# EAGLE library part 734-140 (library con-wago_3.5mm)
Serie 734, Stiftleiste (für Leiterplatten) Einlötstift gerade 1 x 1 mm / Series 734, Male header (for PCBs) Straight solder pin 1 x 1 mm Polzahl / Pole No.: 10 Rastermaß / Pitch: 3.5 mm Bemessungsspannung / Rated Voltage: 160 V Nennstrom / Nominal Current: 10 A Lötstiftlänge: / Solder Pin Length: 4.5 mm Farbe / Color: lichtgrau / light gray Stand: 01.01.2012. Die jeweils aktuellen Daten zu diesem Artikel finden Sie in unserem Produktkatalog, den Sie unter www.wago.com einsehen können. As of: 01/01/2012. Please find the newest data for this article in our product catalogue, which can be viewed under www.wago.com.

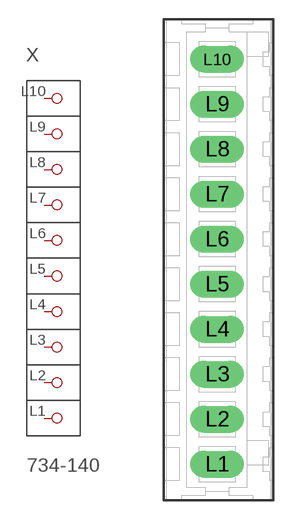
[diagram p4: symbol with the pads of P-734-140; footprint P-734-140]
Designator prefix X

## 734-140  [P-734-140]
L1  P1.1
L2  P2
L3  P3
L4  P4
L5  P5
L6  P6
L7  P7
L8  P8
L9  P9
L10  P10

## Footprint P-734-140 (pad centres in mm)
drill 1.4 long: L1 -0.1,-15.9; L2 -0.1,-12.4; L3 -0.1,-8.9; L4 -0.1,-5.4; L5 -0.1,-1.9; L6 -0.1,1.6; L7 -0.1,5.1; L8 -0.1,8.6; L9 -0.1,12.1; L10 -0.1,15.6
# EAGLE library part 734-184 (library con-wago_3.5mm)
Serie 734, Stiftleiste (für Leiterplatten) Einlötstift abgewinkelt 1 x 1 mm / Series 734, Male header (for PCBs) Angled solder pin 1 x 1 mm Polzahl / Pole No.: 24 Rastermaß / Pitch: 3.5 mm Bemessungsspannung / Rated Voltage: 160 V Nennstrom / Nominal Current: 10 A Lötstiftlänge: / Solder Pin Length: 3.8 mm Farbe / Color: lichtgrau / light gray Stand: 01.01.2012. Die jeweils aktuellen Daten zu diesem Artikel finden Sie in unserem Produktkatalog, den Sie unter www.wago.com einsehen können. As of: 01/01/2012. Please find the newest data for this article in our product catalogue, which can be viewed under www.wago.com.

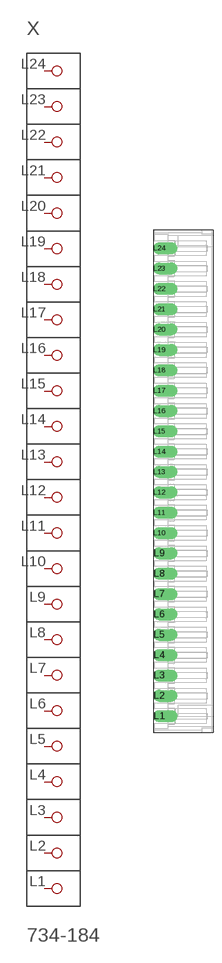
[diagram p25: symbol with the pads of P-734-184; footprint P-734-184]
Designator prefix X

## 734-184  [P-734-184]
L1  P1
L2  P2
L3  P3
L4  P4
L5  P5
L6  P6
L7  P7
L8  P8
L9  P9
L10  P10
L11  P11
L12  P12
L13  P13
L14  P14
L15  P15
L16  P16
L17  P17
L18  P18
L19  P19
L20  P20
L21  P21
L22  P22
L23  P23
L24  P24

## Footprint P-734-184 (pad centres in mm)
drill 1.4 pad 2 offset: L1 -4.15,-40.4; L2 -4.15,-36.9; L3 -4.15,-33.4; L4 -4.15,-29.9; L5 -4.15,-26.4; L6 -4.15,-22.9; L7 -4.15,-19.4; L8 -4.15,-15.9; L9 -4.15,-12.4; L10 -4.15,-8.9; L11 -4.15,-5.4; L12 -4.15,-1.9; L13 -4.15,1.6; L14 -4.15,5.1; L15 -4.15,8.6; L16 -4.15,12.1; L17 -4.15,15.6; L18 -4.15,19.1; L19 -4.15,22.6; L20 -4.15,26.1; L21 -4.15,29.6; L22 -4.15,33.1; L23 -4.15,36.6; L24 -4.15,40.1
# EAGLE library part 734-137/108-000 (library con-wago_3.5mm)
Serie 734, Stiftleiste (für Leiterplatten) Einlötstift gerade 1 x 1 mm / Series 734, Male header (for PCBs) Straight solder pin 1 x 1 mm Polzahl / Pole No.: 7 Bemessungsspannung / Rated Voltage: 160 V Nennstrom / Nominal Current: 10 A Lötstiftlänge: / Solder Pin Length: 4.5 mm Farbe / Color: lichtgrau / light gray Stand: 01.01.2012. Die jeweils aktuellen Daten zu diesem Artikel finden Sie in unserem Produktkatalog, den Sie unter www.wago.com einsehen können. As of: 01/01/2012. Please find the newest data for this article in our product catalogue, which can be viewed under www.wago.com.

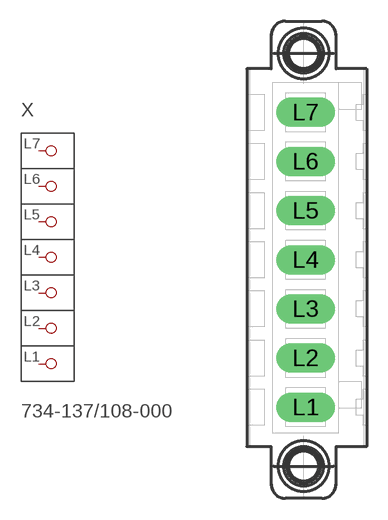
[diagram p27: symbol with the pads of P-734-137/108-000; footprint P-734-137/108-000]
Designator prefix X

## 734-137/108-000  [P-734-137/108-000]
L1  P1
L2  P2
L3  P3
L4  P4
L5  P5
L6  P6
L7  P7

## Footprint P-734-137/108-000 (pad centres in mm)
drill 1.4 long: L1 -0.075,-10.5; L2 -0.075,-7; L3 -0.075,-3.5; L4 -0.075,0; L5 -0.075,3.5; L6 -0.075,7; L7 -0.075,10.5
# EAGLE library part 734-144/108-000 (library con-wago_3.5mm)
Serie 734, Stiftleiste mit geraden Einlötstiften / Series 734, Male connector with straight solder pins Polzahl / Pole No.: 14 Lötstiftlänge: / Solder Pin Length: 4.5 mm Farbe / Color: lichtgrau / light gray Stand: 01.01.2012. Die jeweils aktuellen Daten zu diesem Artikel finden Sie in unserem Produktkatalog, den Sie unter www.wago.com einsehen können. As of: 01/01/2012. Please find the newest data for this article in our product catalogue, which can be viewed under www.wago.com.

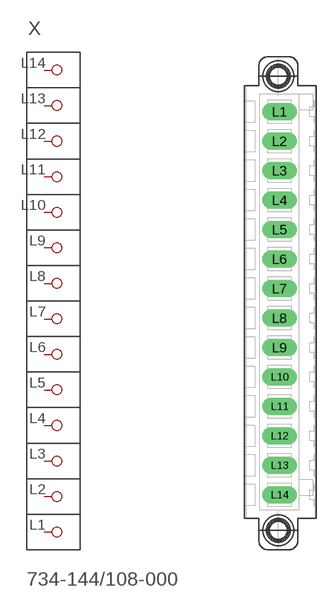
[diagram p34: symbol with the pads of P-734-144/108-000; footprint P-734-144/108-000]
Designator prefix X

## 734-144/108-000  [P-734-144/108-000]
L1  P1
L2  P2
L3  P3
L4  P4
L5  P5
L6  P6
L7  P7
L8  P8
L9  P9
L10  P10
L11  P11
L12  P12
L13  P13
L14  P14

## Footprint P-734-144/108-000 (pad centres in mm)
drill 1.4 long: L1 -0.075,22.75; L2 -0.075,19.25; L3 -0.075,15.75; L4 -0.075,12.25; L5 -0.075,8.75; L6 -0.075,5.25; L7 -0.075,1.75; L8 -0.075,-1.75; L9 -0.075,-5.25; L10 -0.075,-8.75; L11 -0.075,-12.25; L12 -0.075,-15.75; L13 -0.075,-19.25; L14 -0.075,-22.75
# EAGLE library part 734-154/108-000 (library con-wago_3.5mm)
Serie 734, Stiftleiste (für Leiterplatten) Einlötstift gerade 1 x 1 mm / Series 734, Male header (for PCBs) Straight solder pin 1 x 1 mm Polzahl / Pole No.: 24 Bemessungsspannung / Rated Voltage: 160 V Nennstrom / Nominal Current: 10 A Lötstiftlänge: / Solder Pin Length: 4.5 mm Farbe / Color: lichtgrau / light gray Stand: 01.01.2012. Die jeweils aktuellen Daten zu diesem Artikel finden Sie in unserem Produktkatalog, den Sie unter www.wago.com einsehen können. As of: 01/01/2012. Please find the newest data for this article in our product catalogue, which can be viewed under www.wago.com.

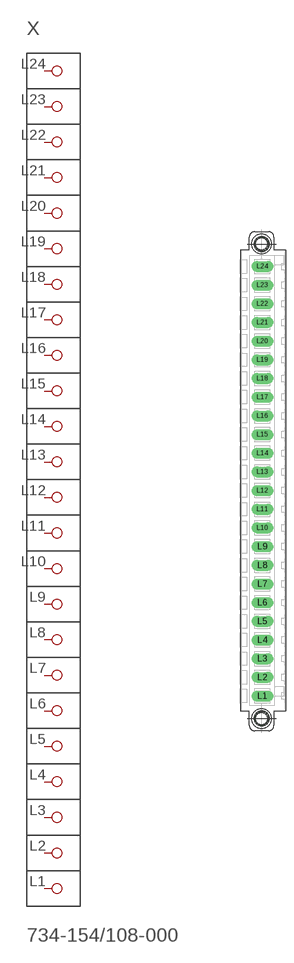
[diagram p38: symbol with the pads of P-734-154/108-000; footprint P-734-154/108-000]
Designator prefix X

## 734-154/108-000  [P-734-154/108-000]
L1  P1
L2  P2
L3  P3
L4  P4
L5  P5
L6  P6
L7  P7
L8  P8
L9  P9
L10  P10
L11  P11
L12  P12
L13  P13
L14  P14
L15  P15
L16  P16
L17  P17
L18  P18
L19  P19
L20  P20
L21  P21
L22  P22
L23  P23
L24  P24

## Footprint P-734-154/108-000 (pad centres in mm)
drill 1.4 long: L1 -0.075,-40.25; L2 -0.075,-36.75; L3 -0.075,-33.25; L4 -0.075,-29.75; L5 -0.075,-26.25; L6 -0.075,-22.75; L7 -0.075,-19.25; L8 -0.075,-15.75; L9 -0.075,-12.25; L10 -0.075,-8.75; L11 -0.075,-5.25; L12 -0.075,-1.75; L13 -0.075,1.75; L14 -0.075,5.25; L15 -0.075,8.75; L16 -0.075,12.25; L17 -0.075,15.75; L18 -0.075,19.25; L19 -0.075,22.75; L20 -0.075,26.25; L21 -0.075,29.75; L22 -0.075,33.25; L23 -0.075,36.75; L24 -0.075,40.25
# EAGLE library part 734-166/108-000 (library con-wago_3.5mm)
Serie 734, Stiftleiste (für Leiterplatten) Einlötstift abgewinkelt 1 x 1 mm / Series 734, Male header (for PCBs) Angled solder pin 1 x 1 mm Polzahl / Pole No.: 6 Bemessungsspannung / Rated Voltage: 160 V Nennstrom / Nominal Current: 10 A Lötstiftlänge: / Solder Pin Length: 3.8 mm Farbe / Color: lichtgrau / light gray Stand: 01.01.2012. Die jeweils aktuellen Daten zu diesem Artikel finden Sie in unserem Produktkatalog, den Sie unter www.wago.com einsehen können. As of: 01/01/2012. Please find the newest data for this article in our product catalogue, which can be viewed under www.wago.com.

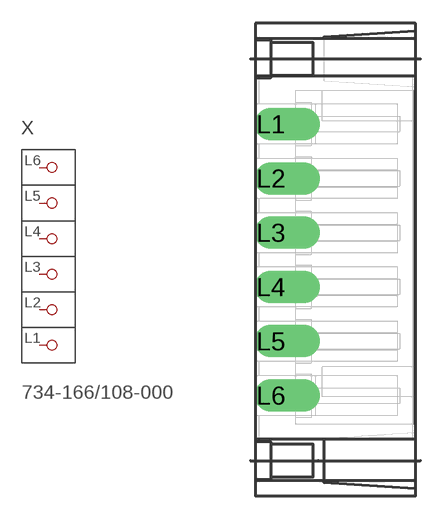
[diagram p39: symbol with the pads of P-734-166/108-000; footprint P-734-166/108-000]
Designator prefix X

## 734-166/108-000  [P-734-166/108-000]
L1  P1
L2  P2
L3  P3
L4  P4
L5  P5
L6  P6

## Footprint P-734-166/108-000 (pad centres in mm)
drill 1.4 pad 2 offset: L1 -4.15,8.75; L2 -4.15,5.25; L3 -4.15,1.75; L4 -4.15,-1.75; L5 -4.15,-5.25; L6 -4.15,-8.75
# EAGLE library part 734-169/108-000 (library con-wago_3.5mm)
Serie 734, Stiftleiste (für Leiterplatten) Einlötstift abgewinkelt 1 x 1 mm / Series 734, Male header (for PCBs) Angled solder pin 1 x 1 mm Polzahl / Pole No.: 9 Bemessungsspannung / Rated Voltage: 160 V Nennstrom / Nominal Current: 10 A Lötstiftlänge: / Solder Pin Length: 3.8 mm Farbe / Color: lichtgrau / light gray Stand: 01.01.2012. Die jeweils aktuellen Daten zu diesem Artikel finden Sie in unserem Produktkatalog, den Sie unter www.wago.com einsehen können. As of: 01/01/2012. Please find the newest data for this article in our product catalogue, which can be viewed under www.wago.com.

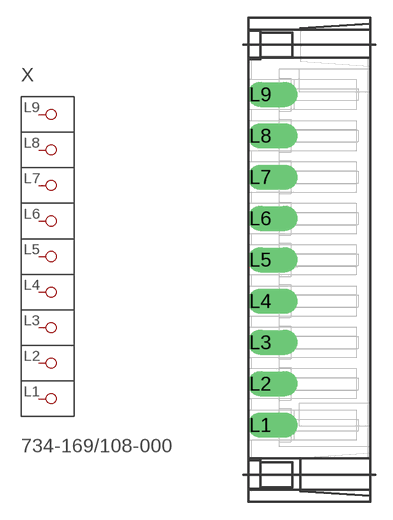
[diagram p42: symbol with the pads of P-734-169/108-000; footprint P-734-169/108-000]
Designator prefix X

## 734-169/108-000  [P-734-169/108-000]
L1  P1
L2  P2
L3  P3
L4  P4
L5  P5
L6  P6
L7  P7
L8  P8
L9  P9

## Footprint P-734-169/108-000 (pad centres in mm)
drill 1.4 pad 2 offset: L1 -4.15,-14; L2 -4.15,-10.5; L3 -4.15,-7; L4 -4.15,-3.5; L5 -4.15,0; L6 -4.15,3.5; L7 -4.15,7; L8 -4.15,10.5; L9 -4.15,14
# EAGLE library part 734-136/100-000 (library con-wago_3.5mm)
Serie 734, Stiftleiste (für Leiterplatten) Einpressstift 0,6 x 0,6 mm / Series 734, Male header (for PCBs) Press-in pin 0.6 x 0.6 mm Polzahl / Pole No.: 6 Rastermaß / Pitch: 3.5 mm Bemessungsspannung / Rated Voltage: 160 V Nennstrom / Nominal Current: 8 A Farbe / Color: lichtgrau / light gray Stand: 01.01.2012. Die jeweils aktuellen Daten zu diesem Artikel finden Sie in unserem Produktkatalog, den Sie unter www.wago.com einsehen können. As of: 01/01/2012. Please find the newest data for this article in our product catalogue, which can be viewed under www.wago.com.

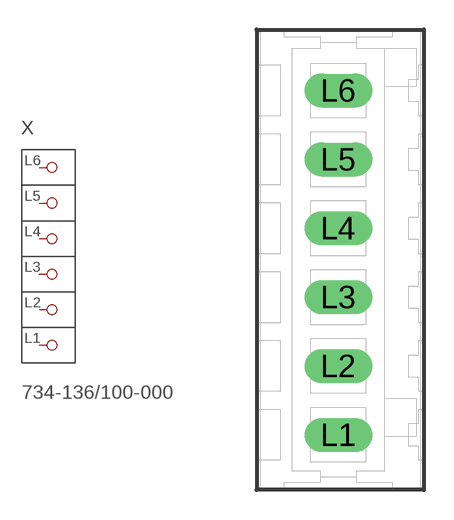
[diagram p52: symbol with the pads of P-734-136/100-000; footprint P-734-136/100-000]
Designator prefix X

## 734-136/100-000  [P-734-136/100-000]
L1  P1
L2  P2
L3  P3
L4  P4
L5  P5
L6  P6

## Footprint P-734-136/100-000 (pad centres in mm)
drill 1.15 long: L1 -0.1,-8.9; L2 -0.1,-5.4; L3 -0.1,-1.9; L4 -0.1,1.6; L5 -0.1,5.1; L6 -0.1,8.6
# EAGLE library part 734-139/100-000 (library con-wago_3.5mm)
Serie 734, Stiftleiste (für Leiterplatten) Einpressstift 0,6 x 0,6 mm / Series 734, Male header (for PCBs) Press-in pin 0.6 x 0.6 mm Polzahl / Pole No.: 9 Rastermaß / Pitch: 3.5 mm Bemessungsspannung / Rated Voltage: 160 V Nennstrom / Nominal Current: 8 A Farbe / Color: lichtgrau / light gray Stand: 01.01.2012. Die jeweils aktuellen Daten zu diesem Artikel finden Sie in unserem Produktkatalog, den Sie unter www.wago.com einsehen können. As of: 01/01/2012. Please find the newest data for this article in our product catalogue, which can be viewed under www.wago.com.

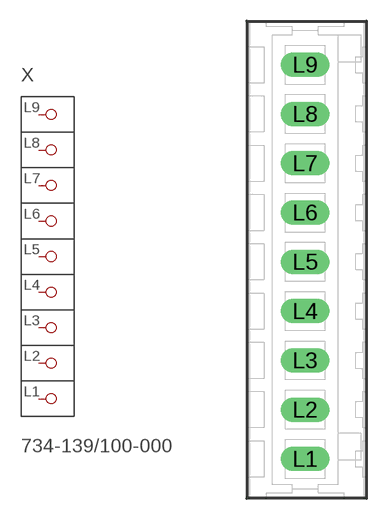
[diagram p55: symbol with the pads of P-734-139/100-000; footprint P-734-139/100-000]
Designator prefix X

## 734-139/100-000  [P-734-139/100-000]
L1  P1
L2  P2
L3  P3
L4  P4
L5  P5
L6  P6
L7  P7
L8  P8
L9  P9

## Footprint P-734-139/100-000 (pad centres in mm)
drill 1.15 long: L1 -0.1,-14.15; L2 -0.1,-10.65; L3 -0.1,-7.15; L4 -0.1,-3.65; L5 -0.1,-0.15; L6 -0.1,3.35; L7 -0.1,6.85; L8 -0.1,10.35; L9 -0.1,13.85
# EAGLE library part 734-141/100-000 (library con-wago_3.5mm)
Serie 734, Stiftleiste (für Leiterplatten) Einpressstift 0,6 x 0,6 mm / Series 734, Male header (for PCBs) Press-in pin 0.6 x 0.6 mm Polzahl / Pole No.: 11 Bemessungsspannung / Rated Voltage: 160 V Nennstrom / Nominal Current: 10 A Farbe / Color: lichtgrau / light gray Stand: 01.01.2012. Die jeweils aktuellen Daten zu diesem Artikel finden Sie in unserem Produktkatalog, den Sie unter www.wago.com einsehen können. As of: 01/01/2012. Please find the newest data for this article in our product catalogue, which can be viewed under www.wago.com.

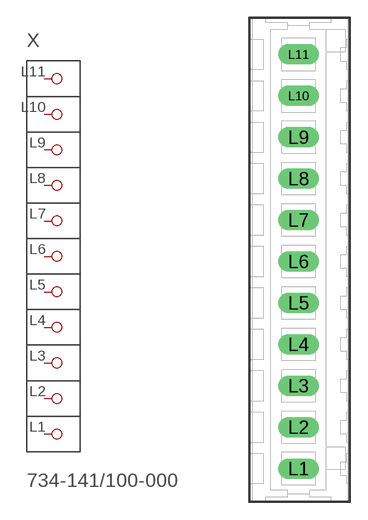
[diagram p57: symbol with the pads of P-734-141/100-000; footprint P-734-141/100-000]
Designator prefix X

## 734-141/100-000  [P-734-141/100-000]
L1  P1
L2  P2
L3  P3
L4  P4
L5  P5
L6  P6
L7  P7
L8  P8
L9  P9
L10  P10
L11  P11

## Footprint P-734-141/100-000 (pad centres in mm)
drill 1.15 long: L1 -0.1,-17.65; L2 -0.1,-14.15; L3 -0.1,-10.65; L4 -0.1,-7.15; L5 -0.1,-3.65; L6 -0.1,-0.15; L7 -0.1,3.35; L8 -0.1,6.85; L9 -0.1,10.35; L10 -0.1,13.85; L11 -0.1,17.35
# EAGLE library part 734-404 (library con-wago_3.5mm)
Serie 734, Doppelstock-Stiftleisten Einlötstift abgewinkelt 1 x 1 mm / Series 734, Double-deck male headers Angled solder pin 1 x 1 mm Polzahl / Pole No.: 4 Rastermaß / Pitch: 3.5 mm Bemessungsspannung / Rated Voltage: 160 V Nennstrom / Nominal Current: 10 A Lötstiftlänge: / Solder Pin Length: 3.6 mm Farbe / Color: lichtgrau / light gray Stand: 01.01.2012. Die jeweils aktuellen Daten zu diesem Artikel finden Sie in unserem Produktkatalog, den Sie unter www.wago.com einsehen können. As of: 01/01/2012. Please find the newest data for this article in our product catalogue, which can be viewed under www.wago.com.

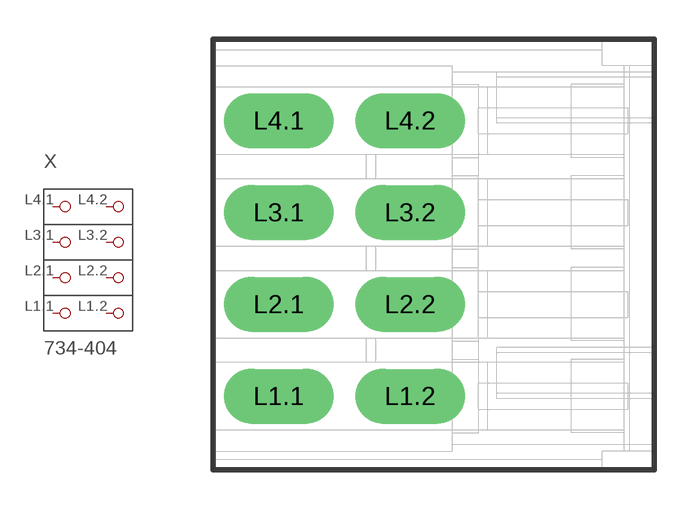
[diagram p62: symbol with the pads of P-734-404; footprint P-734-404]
Designator prefix X

## 734-404  [P-734-404]
L1.1  P1.1
L1.2  P1.2
L2.1  P2.1
L2.2  P2.2
L3.1  P3.1
L3.2  P3.2
L4.1  P4.1
L4.2  P4.2

## Footprint P-734-404 (pad centres in mm)
drill 1.4 long: L1.1 -5.9,-5.4; L1.2 -0.9,-5.4; L2.1 -5.9,-1.9; L2.2 -0.9,-1.9; L3.1 -5.9,1.6; L3.2 -0.9,1.6; L4.1 -5.9,5.1; L4.2 -0.9,5.1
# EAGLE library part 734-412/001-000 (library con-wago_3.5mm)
Serie 734, Doppelstock-Stiftleisten Einlötstift abgewinkelt 1 x 1 mm / Series 734, Double-deck male headers Angled solder pin 1 x 1 mm Polzahl / Pole No.: 12 Rastermaß / Pitch: 3.5 mm Bemessungsspannung / Rated Voltage: 160 V Nennstrom / Nominal Current: 10 A Lötstiftlänge: / Solder Pin Length: 3.6 mm Farbe / Color: lichtgrau / light gray Stand: 01.01.2012. Die jeweils aktuellen Daten zu diesem Artikel finden Sie in unserem Produktkatalog, den Sie unter www.wago.com einsehen können. As of: 01/01/2012. Please find the newest data for this article in our product catalogue, which can be viewed under www.wago.com.

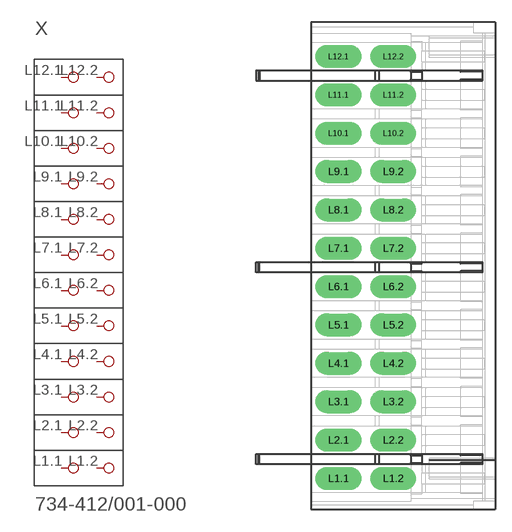
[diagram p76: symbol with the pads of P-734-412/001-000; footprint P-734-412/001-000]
Designator prefix X

## 734-412/001-000  [P-734-412/001-000]
L1.1  P1.1
L1.2  P1.2
L2.1  P2.1
L2.2  P2.2
L3.1  P3.1
L3.2  P3.2
L4.1  P4.1
L4.2  P4.2
L5.1  P5.1
L5.2  P5.2
L6.1  P6.1
L6.2  P6.2
L7.1  P7.1
L7.2  P7.2
L8.1  P8.1
L8.2  P8.2
L9.1  P9.1
L9.2  P9.2
L10.1  P10.1
L10.2  P10.2
L11.1  P11.1
L11.2  P11.2
L12.1  P12.1
L12.2  P12.2

## Footprint P-734-412/001-000 (pad centres in mm)
drill 1.4 long: L1.1 -3.4,-19.4; L1.2 1.6,-19.4; L2.1 -3.4,-15.9; L2.2 1.6,-15.9; L3.1 -3.4,-12.4; L3.2 1.6,-12.4; L4.1 -3.4,-8.9; L4.2 1.6,-8.9; L5.1 -3.4,-5.4; L5.2 1.6,-5.4; L6.1 -3.4,-1.9; L6.2 1.6,-1.9; L7.1 -3.4,1.6; L7.2 1.6,1.6; L8.1 -3.4,5.1; L8.2 1.6,5.1; L9.1 -3.4,8.6; L9.2 1.6,8.6; L10.1 -3.4,12.1; L10.2 1.6,12.1; L11.1 -3.4,15.6; L11.2 1.6,15.6; L12.1 -3.4,19.1; L12.2 1.6,19.1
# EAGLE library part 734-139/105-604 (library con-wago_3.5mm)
Serie 734, Stiftleiste (für Leiterplatten) Einlötstift gerade 1 x 1 mm / Series 734, Male header (for PCBs) Straight solder pin 1 x 1 mm Polzahl / Pole No.: 9 Bemessungsspannung / Rated Voltage: 160 V Nennstrom / Nominal Current: 10 A Lötstiftlänge: / Solder Pin Length: 2.4 mm Farbe / Color: schwarz / black Stand: 01.01.2012. Die jeweils aktuellen Daten zu diesem Artikel finden Sie in unserem Produktkatalog, den Sie unter www.wago.com einsehen können. As of: 01/01/2012. Please find the newest data for this article in our product catalogue, which can be viewed under www.wago.com.

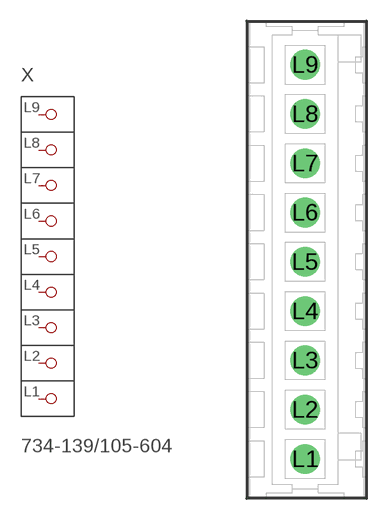
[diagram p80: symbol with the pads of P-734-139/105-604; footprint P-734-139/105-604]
Designator prefix X

## 734-139/105-604  [P-734-139/105-604]
L1  P1
L2  P2
L3  P3
L4  P4
L5  P5
L6  P6
L7  P7
L8  P8
L9  P9

## Footprint P-734-139/105-604 (pad centres in mm)
drill 1.4 round: L1 -0.1,-14.15; L2 -0.102,-10.645; L3 -0.1,-7.147; L4 -0.101,-3.646; L5 -0.111,-0.146; L6 -0.101,3.354; L7 -0.101,6.854; L8 -0.101,10.354; L9 -0.101,13.854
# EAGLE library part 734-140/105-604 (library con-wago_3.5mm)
Serie 734, Stiftleiste (für Leiterplatten) Einlötstift gerade 1 x 1 mm / Series 734, Male header (for PCBs) Straight solder pin 1 x 1 mm Polzahl / Pole No.: 10 Rastermaß / Pitch: 3.5 mm Bemessungsspannung / Rated Voltage: 160 V Nennstrom / Nominal Current: 10 A Lötstiftlänge: / Solder Pin Length: 2.4 mm Farbe / Color: schwarz / black Stand: 01.01.2012. Die jeweils aktuellen Daten zu diesem Artikel finden Sie in unserem Produktkatalog, den Sie unter www.wago.com einsehen können. As of: 01/01/2012. Please find the newest data for this article in our product catalogue, which can be viewed under www.wago.com.

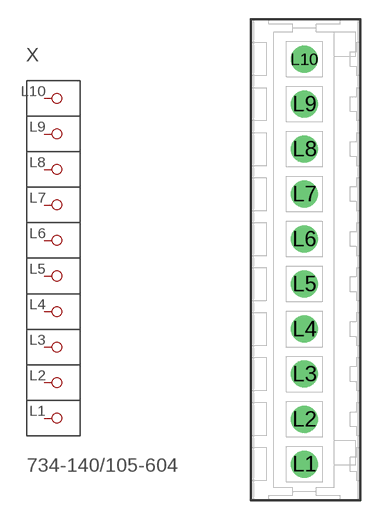
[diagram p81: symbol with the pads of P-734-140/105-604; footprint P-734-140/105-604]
Designator prefix X

## 734-140/105-604  [P-734-140/105-604]
L1  P1.1
L2  P2
L3  P3
L4  P4
L5  P5
L6  P6
L7  P7
L8  P8
L9  P9
L10  P10

## Footprint P-734-140/105-604 (pad centres in mm)
drill 1.4 round: L1 -0.1,-15.896; L2 -0.1,-12.404; L3 -0.093,-8.89; L4 -0.091,-5.392; L5 -0.092,-1.891; L6 -0.102,1.609; L7 -0.092,5.109; L8 -0.092,8.609; L9 -0.092,12.109; L10 -0.092,15.609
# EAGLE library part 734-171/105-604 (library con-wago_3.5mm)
Serie 734, Stiftleiste (für Leiterplatten) Einlötstift abgewinkelt 1 x 1 mm / Series 734, Male header (for PCBs) Angled solder pin 1 x 1 mm Polzahl / Pole No.: 11 Bemessungsspannung / Rated Voltage: 160 V Nennstrom / Nominal Current: 10 A Lötstiftlänge: / Solder Pin Length: 2.4 mm Farbe / Color: schwarz / black Stand: 01.01.2012. Die jeweils aktuellen Daten zu diesem Artikel finden Sie in unserem Produktkatalog, den Sie unter www.wago.com einsehen können. As of: 01/01/2012. Please find the newest data for this article in our product catalogue, which can be viewed under www.wago.com.

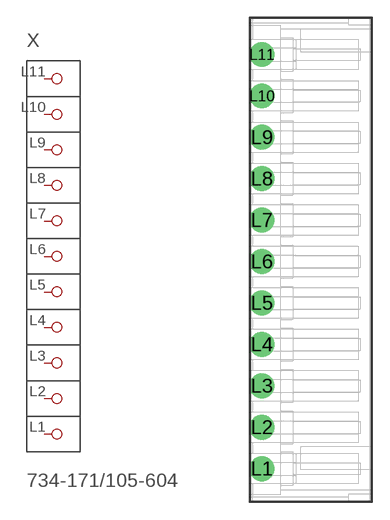
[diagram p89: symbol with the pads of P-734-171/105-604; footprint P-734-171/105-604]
Designator prefix X

## 734-171/105-604  [P-734-171/105-604]
L1  P1
L2  P2
L3  P3
L4  P4
L5  P5
L6  P6
L7  P7
L8  P8
L9  P9
L10  P10
L11  P11

## Footprint P-734-171/105-604 (pad centres in mm)
drill 1.4 round: L1 -4.15,-17.65; L2 -4.15,-14.15; L3 -4.15,-10.65; L4 -4.15,-7.15; L5 -4.15,-3.65; L6 -4.15,-0.15; L7 -4.15,3.35; L8 -4.15,6.85; L9 -4.15,10.35; L10 -4.15,13.85; L11 -4.15,17.35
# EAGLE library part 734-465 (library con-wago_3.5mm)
Serie 734, Federleiste mit geraden Einlötstiften / Series 734, Female connector with straight solder pins Polzahl / Pole No.: 5 Bemessungsspannung / Rated Voltage: 160 V Nennstrom / Nominal Current: 10 A Lötstiftlänge: / Solder Pin Length: 3.8 mm Farbe / Color: lichtgrau / light gray Stand: 01.01.2012. Die jeweils aktuellen Daten zu diesem Artikel finden Sie in unserem Produktkatalog, den Sie unter www.wago.com einsehen können. As of: 01/01/2012. Please find the newest data for this article in our product catalogue, which can be viewed under www.wago.com.

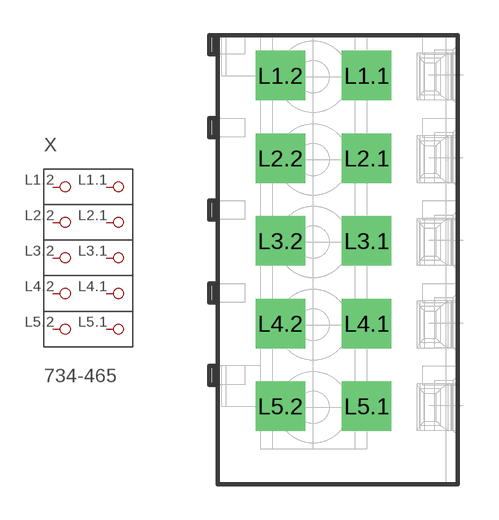
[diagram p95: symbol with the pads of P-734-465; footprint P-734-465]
Designator prefix X

## 734-465  [P-734-465]
L1.1  P1.1
L1.2  P1.2
L2.1  P2.1
L2.2  P2.2
L3.1  P3.1
L3.2  P3.2
L4.1  P4.1
L4.2  P4.2
L5.1  P5.1
L5.2  P5.2

## Footprint P-734-465 (pad centres in mm)
drill 1.4 square: L1.1 1.284,7.8; L1.2 -2.366,7.8; L2.1 1.284,4.3; L2.2 -2.366,4.3; L3.1 1.284,0.8; L3.2 -2.366,0.8; L4.1 1.284,-2.7; L4.2 -2.366,-2.7; L5.1 1.284,-6.2; L5.2 -2.366,-6.2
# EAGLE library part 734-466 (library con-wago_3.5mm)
Serie 734, Federleiste mit geraden Einlötstiften / Series 734, Female connector with straight solder pins Polzahl / Pole No.: 6 Bemessungsspannung / Rated Voltage: 160 V Nennstrom / Nominal Current: 10 A Lötstiftlänge: / Solder Pin Length: 3.8 mm Farbe / Color: lichtgrau / light gray Stand: 01.01.2012. Die jeweils aktuellen Daten zu diesem Artikel finden Sie in unserem Produktkatalog, den Sie unter www.wago.com einsehen können. As of: 01/01/2012. Please find the newest data for this article in our product catalogue, which can be viewed under www.wago.com.

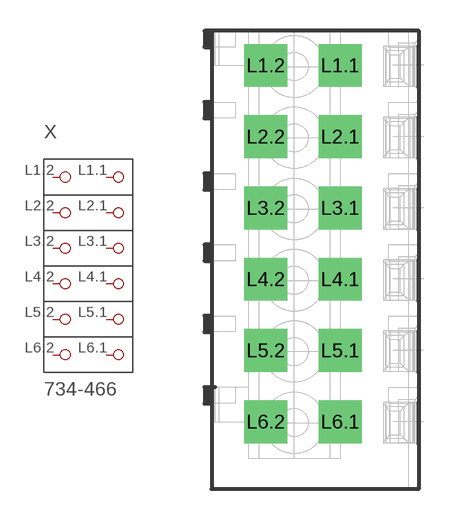
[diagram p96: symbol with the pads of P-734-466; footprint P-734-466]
Designator prefix X

## 734-466  [P-734-466]
L1.1  P1.1
L1.2  P1.2
L2.1  P2.1
L2.2  P2.2
L3.1  P3.1
L3.2  P3.2
L4.1  P4.1
L4.2  P4.2
L5.1  P5.1
L5.2  P5.2
L6.1  P6.1
L6.2  P6.2

## Footprint P-734-466 (pad centres in mm)
drill 1.4 square: L1.1 1.269,9.544; L1.2 -2.381,9.544; L2.1 1.269,6.044; L2.2 -2.381,6.044; L3.1 1.269,2.544; L3.2 -2.381,2.544; L4.1 1.269,-0.956; L4.2 -2.381,-0.956; L5.1 1.269,-4.456; L5.2 -2.381,-4.456; L6.1 1.269,-7.956; L6.2 -2.381,-7.956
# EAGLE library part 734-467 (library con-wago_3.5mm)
Serie 734, Federleiste mit geraden Einlötstiften / Series 734, Female connector with straight solder pins Polzahl / Pole No.: 7 Bemessungsspannung / Rated Voltage: 160 V Nennstrom / Nominal Current: 10 A Lötstiftlänge: / Solder Pin Length: 3.8 mm Farbe / Color: lichtgrau / light gray Stand: 01.01.2012. Die jeweils aktuellen Daten zu diesem Artikel finden Sie in unserem Produktkatalog, den Sie unter www.wago.com einsehen können. As of: 01/01/2012. Please find the newest data for this article in our product catalogue, which can be viewed under www.wago.com.

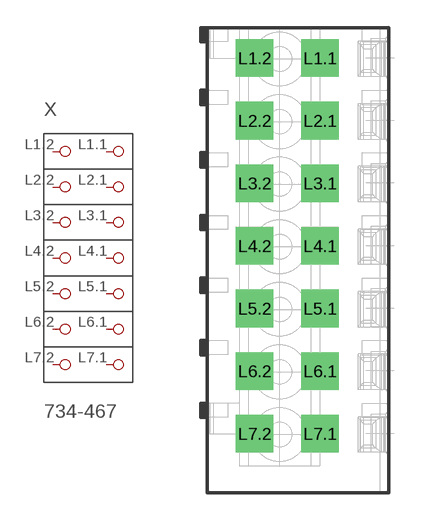
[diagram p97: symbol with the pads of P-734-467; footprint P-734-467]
Designator prefix X

## 734-467  [P-734-467]
L1.1  P1.1
L1.2  P1.2
L2.1  P2.1
L2.2  P2.2
L3.1  P3.1
L3.2  P3.2
L4.1  P4.1
L4.2  P4.2
L5.1  P5.1
L5.2  P5.2
L6.1  P6.1
L6.2  P6.2
L7.1  P7.1
L7.2  P7.2

## Footprint P-734-467 (pad centres in mm)
drill 1.4 square: L1.1 1.253,11.278; L1.2 -2.397,11.278; L2.1 1.253,7.778; L2.2 -2.397,7.778; L3.1 1.253,4.278; L3.2 -2.397,4.278; L4.1 1.253,0.778; L4.2 -2.397,0.778; L5.1 1.253,-2.722; L5.2 -2.397,-2.722; L6.1 1.253,-6.222; L6.2 -2.397,-6.222; L7.1 1.253,-9.722; L7.2 -2.397,-9.722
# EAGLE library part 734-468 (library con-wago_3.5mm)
Serie 734, Federleiste mit geraden Einlötstiften / Series 734, Female connector with straight solder pins Polzahl / Pole No.: 8 Bemessungsspannung / Rated Voltage: 160 V Nennstrom / Nominal Current: 10 A Lötstiftlänge: / Solder Pin Length: 3.8 mm Farbe / Color: lichtgrau / light gray Stand: 01.01.2012. Die jeweils aktuellen Daten zu diesem Artikel finden Sie in unserem Produktkatalog, den Sie unter www.wago.com einsehen können. As of: 01/01/2012. Please find the newest data for this article in our product catalogue, which can be viewed under www.wago.com.

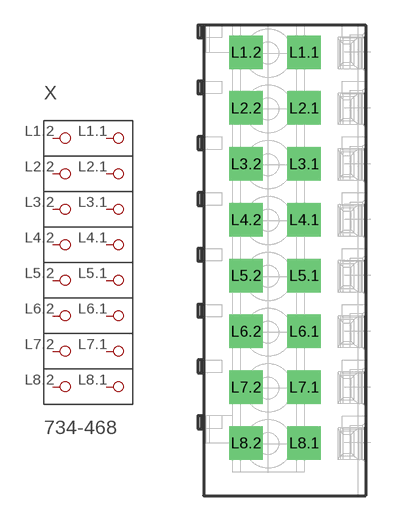
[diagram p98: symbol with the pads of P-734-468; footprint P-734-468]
Designator prefix X

## 734-468  [P-734-468]
L1.1  P1.1
L1.2  P1.2
L2.1  P2.1
L2.2  P2.2
L3.1  P3.1
L3.2  P3.2
L4.1  P4.1
L4.2  P4.2
L5.1  P5.1
L5.2  P5.2
L6.1  P6.1
L6.2  P6.2
L7.1  P7.1
L7.2  P7.2
L8.1  P8.1
L8.2  P8.2

## Footprint P-734-468 (pad centres in mm)
drill 1.4 square: L1.1 1.236,13.012; L1.2 -2.413,13.012; L2.1 1.236,9.512; L2.2 -2.413,9.512; L3.1 1.236,6.012; L3.2 -2.413,6.012; L4.1 1.236,2.512; L4.2 -2.413,2.512; L5.1 1.236,-0.988; L5.2 -2.413,-0.988; L6.1 1.236,-4.488; L6.2 -2.413,-4.488; L7.1 1.236,-7.988; L7.2 -2.413,-7.988; L8.1 1.236,-11.488; L8.2 -2.413,-11.488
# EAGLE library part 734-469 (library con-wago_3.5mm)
Serie 734, Federleiste mit geraden Einlötstiften / Series 734, Female connector with straight solder pins Polzahl / Pole No.: 9 Bemessungsspannung / Rated Voltage: 160 V Nennstrom / Nominal Current: 10 A Lötstiftlänge: / Solder Pin Length: 3.8 mm Farbe / Color: lichtgrau / light gray Stand: 01.01.2012. Die jeweils aktuellen Daten zu diesem Artikel finden Sie in unserem Produktkatalog, den Sie unter www.wago.com einsehen können. As of: 01/01/2012. Please find the newest data for this article in our product catalogue, which can be viewed under www.wago.com.

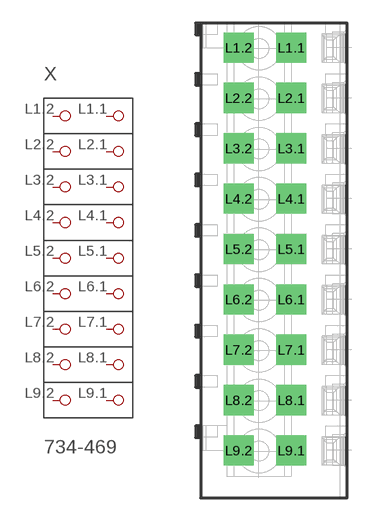
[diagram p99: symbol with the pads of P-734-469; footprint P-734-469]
Designator prefix X

## 734-469  [P-734-469]
L1.1  P1.1
L1.2  P1.2
L2.1  P2.1
L2.2  P2.2
L3.1  P3.1
L3.2  P3.2
L4.1  P4.1
L4.2  P4.2
L5.1  P5.1
L5.2  P5.2
L6.1  P6.1
L6.2  P6.2
L7.1  P7.1
L7.2  P7.2
L8.1  P8.1
L8.2  P8.2
L9.1  P9.1
L9.2  P9.2

## Footprint P-734-469 (pad centres in mm)
drill 1.4 square: L1.1 1.22,14.745; L1.2 -2.43,14.745; L2.1 1.22,11.245; L2.2 -2.43,11.245; L3.1 1.22,7.745; L3.2 -2.43,7.745; L4.1 1.22,4.245; L4.2 -2.43,4.245; L5.1 1.22,0.745; L5.2 -2.43,0.745; L6.1 1.22,-2.755; L6.2 -2.43,-2.755; L7.1 1.22,-6.255; L7.2 -2.43,-6.255; L8.1 1.22,-9.755; L8.2 -2.43,-9.755; L9.1 1.22,-13.255; L9.2 -2.43,-13.255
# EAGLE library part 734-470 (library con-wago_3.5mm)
Serie 734, Federleiste mit geraden Einlötstiften / Series 734, Female connector with straight solder pins Polzahl / Pole No.: 10 Bemessungsspannung / Rated Voltage: 160 V Nennstrom / Nominal Current: 10 A Lötstiftlänge: / Solder Pin Length: 3.8 mm Farbe / Color: lichtgrau / light gray Stand: 01.01.2012. Die jeweils aktuellen Daten zu diesem Artikel finden Sie in unserem Produktkatalog, den Sie unter www.wago.com einsehen können. As of: 01/01/2012. Please find the newest data for this article in our product catalogue, which can be viewed under www.wago.com.

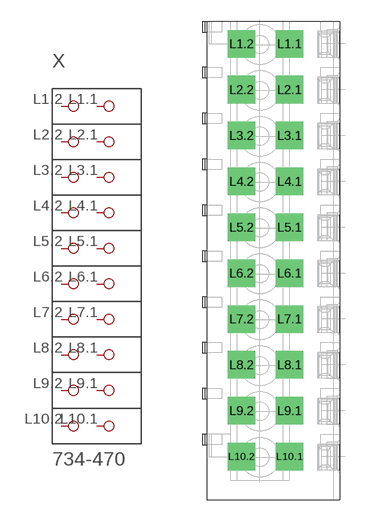
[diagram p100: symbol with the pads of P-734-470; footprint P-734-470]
Designator prefix X

## 734-470  [P-734-470]
L1.1  P1.1
L1.2  P1.2
L2.1  P2.1
L2.2  P2.2
L3.1  P3.1
L3.2  P3.2
L4.1  P4.1
L4.2  P4.2
L5.1  P5.1
L5.2  P5.2
L6.1  P6.1
L6.2  P6.2
L7.1  P7.1
L7.2  P7.2
L8.1  P8.1
L8.2  P8.2
L9.1  P9.1
L9.2  P9.2
L10.1  P10.1
L10.2  P10.2

## Footprint P-734-470 (pad centres in mm)
drill 1.4 square: L1.1 1.204,16.479; L1.2 -2.446,16.479; L2.1 1.204,12.979; L2.2 -2.446,12.979; L3.1 1.204,9.479; L3.2 -2.446,9.479; L4.1 1.204,5.979; L4.2 -2.446,5.979; L5.1 1.204,2.478; L5.2 -2.446,2.478; L6.1 1.204,-1.022; L6.2 -2.446,-1.022; L7.1 1.204,-4.521; L7.2 -2.446,-4.521; L8.1 1.204,-8.021; L8.2 -2.446,-8.021; L9.1 1.204,-11.521; L9.2 -2.446,-11.521; L10.1 1.204,-15.021; L10.2 -2.446,-15.021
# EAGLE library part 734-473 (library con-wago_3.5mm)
Serie 734, Federleiste mit geraden Einlötstiften / Series 734, Female connector with straight solder pins Polzahl / Pole No.: 13 Bemessungsspannung / Rated Voltage: 160 V Nennstrom / Nominal Current: 10 A Lötstiftlänge: / Solder Pin Length: 3.8 mm Farbe / Color: lichtgrau / light gray Stand: 01.01.2012. Die jeweils aktuellen Daten zu diesem Artikel finden Sie in unserem Produktkatalog, den Sie unter www.wago.com einsehen können. As of: 01/01/2012. Please find the newest data for this article in our product catalogue, which can be viewed under www.wago.com.

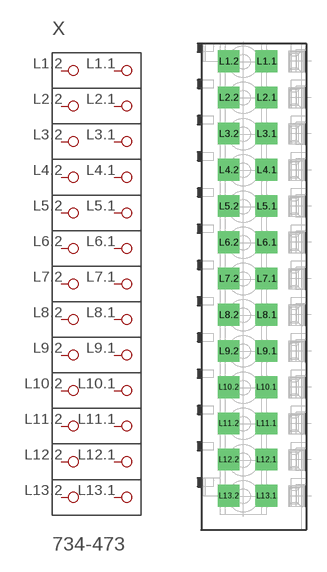
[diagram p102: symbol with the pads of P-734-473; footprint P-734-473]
Designator prefix X

## 734-473  [P-734-473]
L1.1  P1.1
L1.2  P1.2
L2.1  P2.1
L2.2  P2.2
L3.1  P3.1
L3.2  P3.2
L4.1  P4.1
L4.2  P4.2
L5.1  P5.1
L5.2  P5.2
L6.1  P6.1
L6.2  P6.2
L7.1  P7.1
L7.2  P7.2
L8.1  P8.1
L8.2  P8.2
L9.1  P9.1
L9.2  P9.2
L10.1  P10.1
L10.2  P10.2
L11.1  P11.1
L11.2  P11.2
L12.1  P12.1
L12.2  P12.2
L13.1  P13.1
L13.2  P13.2

## Footprint P-734-473 (pad centres in mm)
drill 1.4 square: L1.1 1.153,21.678; L1.2 -2.497,21.678; L2.1 1.153,18.178; L2.2 -2.497,18.178; L3.1 1.153,14.678; L3.2 -2.497,14.678; L4.1 1.153,11.178; L4.2 -2.497,11.178; L5.1 1.153,7.678; L5.2 -2.497,7.678; L6.1 1.153,4.178; L6.2 -2.497,4.178; L7.1 1.153,0.678; L7.2 -2.497,0.678; L8.1 1.153,-2.822; L8.2 -2.497,-2.822; L9.1 1.153,-6.322; L9.2 -2.497,-6.322; L10.1 1.153,-9.822; L10.2 -2.497,-9.822; L11.1 1.153,-13.322; L11.2 -2.497,-13.322; L12.1 1.153,-16.822; L12.2 -2.497,-16.822; L13.1 1.153,-20.322; L13.2 -2.497,-20.322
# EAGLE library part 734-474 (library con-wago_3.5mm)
Serie 734, Federleiste mit geraden Einlötstiften / Series 734, Female connector with straight solder pins Polzahl / Pole No.: 14 Bemessungsspannung / Rated Voltage: 160 V Nennstrom / Nominal Current: 10 A Lötstiftlänge: / Solder Pin Length: 3.8 mm Farbe / Color: lichtgrau / light gray Stand: 01.01.2012. Die jeweils aktuellen Daten zu diesem Artikel finden Sie in unserem Produktkatalog, den Sie unter www.wago.com einsehen können. As of: 01/01/2012. Please find the newest data for this article in our product catalogue, which can be viewed under www.wago.com.

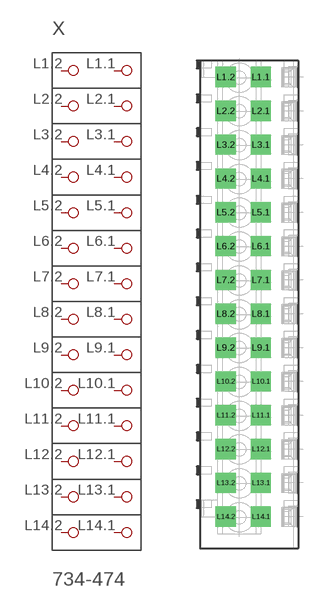
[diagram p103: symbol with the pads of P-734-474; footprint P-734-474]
Designator prefix X

## 734-474  [P-734-474]
L1.1  P1.1
L1.2  P1.2
L2.1  P2.1
L2.2  P2.2
L3.1  P3.1
L3.2  P3.2
L4.1  P4.1
L4.2  P4.2
L5.1  P5.1
L5.2  P5.2
L6.1  P6.1
L6.2  P6.2
L7.1  P7.1
L7.2  P7.2
L8.1  P8.1
L8.2  P8.2
L9.1  P9.1
L9.2  P9.2
L10.1  P10.1
L10.2  P10.2
L11.1  P11.1
L11.2  P11.2
L12.1  P12.1
L12.2  P12.2
L13.1  P13.1
L13.2  P13.2
L14.1  P14.1
L14.2  P14.2

## Footprint P-734-474 (pad centres in mm)
drill 1.4 square: L1.1 1.136,23.411; L1.2 -2.514,23.411; L2.1 1.136,19.911; L2.2 -2.514,19.911; L3.1 1.136,16.411; L3.2 -2.514,16.411; L4.1 1.136,12.911; L4.2 -2.514,12.911; L5.1 1.136,9.411; L5.2 -2.514,9.411; L6.1 1.136,5.911; L6.2 -2.514,5.911; L7.1 1.136,2.411; L7.2 -2.514,2.411; L8.1 1.136,-1.089; L8.2 -2.514,-1.089; L9.1 1.136,-4.589; L9.2 -2.514,-4.589; L10.1 1.136,-8.089; L10.2 -2.514,-8.089; L11.1 1.136,-11.589; L11.2 -2.514,-11.589; L12.1 1.136,-15.089; L12.2 -2.514,-15.089; L13.1 1.136,-18.589; L13.2 -2.514,-18.589; L14.1 1.136,-22.089; L14.2 -2.514,-22.089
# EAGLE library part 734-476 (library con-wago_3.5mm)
Serie 734, Federleiste mit geraden Einlötstiften / Series 734, Female connector with straight solder pins Polzahl / Pole No.: 16 Bemessungsspannung / Rated Voltage: 160 V Nennstrom / Nominal Current: 10 A Lötstiftlänge: / Solder Pin Length: 3.8 mm Farbe / Color: lichtgrau / light gray Stand: 01.01.2012. Die jeweils aktuellen Daten zu diesem Artikel finden Sie in unserem Produktkatalog, den Sie unter www.wago.com einsehen können. As of: 01/01/2012. Please find the newest data for this article in our product catalogue, which can be viewed under www.wago.com.

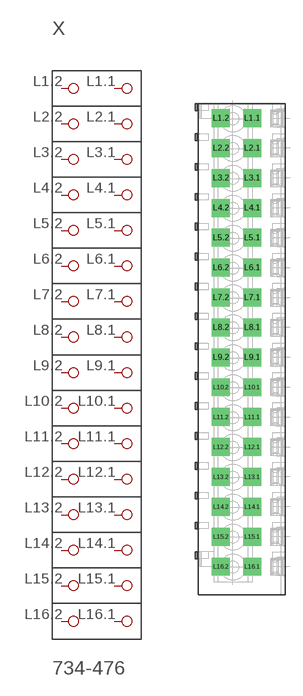
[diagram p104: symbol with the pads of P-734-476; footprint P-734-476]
Designator prefix X

## 734-476  [P-734-476]
L1.1  P1.1
L1.2  P1.2
L2.1  P2.1
L2.2  P2.2
L3.1  P3.1
L3.2  P3.2
L4.1  P4.1
L4.2  P4.2
L5.1  P5.1
L5.2  P5.2
L6.1  P6.1
L6.2  P6.2
L7.1  P7.1
L7.2  P7.2
L8.1  P8.1
L8.2  P8.2
L9.1  P9.1
L9.2  P9.2
L10.1  P10.1
L10.2  P10.2
L11.1  P11.1
L11.2  P11.2
L12.1  P12.1
L12.2  P12.2
L13.1  P13.1
L13.2  P13.2
L14.1  P14.1
L14.2  P14.2
L15.1  P15.1
L15.2  P15.2
L16.1  P16.1
L16.2  P16.2

## Footprint P-734-476 (pad centres in mm)
drill 1.4 square: L1.1 1.102,26.877; L1.2 -2.548,26.877; L2.1 1.102,23.377; L2.2 -2.548,23.377; L3.1 1.102,19.877; L3.2 -2.548,19.877; L4.1 1.102,16.377; L4.2 -2.548,16.377; L5.1 1.102,12.877; L5.2 -2.548,12.877; L6.1 1.102,9.377; L6.2 -2.548,9.377; L7.1 1.102,5.877; L7.2 -2.548,5.877; L8.1 1.102,2.377; L8.2 -2.548,2.377; L9.1 1.102,-1.123; L9.2 -2.548,-1.123; L10.1 1.102,-4.623; L10.2 -2.548,-4.623; L11.1 1.102,-8.123; L11.2 -2.548,-8.123; L12.1 1.102,-11.623; L12.2 -2.548,-11.623; L13.1 1.102,-15.123; L13.2 -2.548,-15.123; L14.1 1.102,-18.623; L14.2 -2.548,-18.623; L15.1 1.102,-22.123; L15.2 -2.548,-22.123; L16.1 1.102,-25.623; L16.2 -2.548,-25.623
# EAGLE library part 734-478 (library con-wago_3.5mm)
Serie 734, Federleiste mit geraden Einlötstiften / Series 734, Female connector with straight solder pins Polzahl / Pole No.: 18 Bemessungsspannung / Rated Voltage: 160 V Nennstrom / Nominal Current: 10 A Lötstiftlänge: / Solder Pin Length: 3.8 mm Farbe / Color: lichtgrau / light gray Stand: 01.01.2012. Die jeweils aktuellen Daten zu diesem Artikel finden Sie in unserem Produktkatalog, den Sie unter www.wago.com einsehen können. As of: 01/01/2012. Please find the newest data for this article in our product catalogue, which can be viewed under www.wago.com.

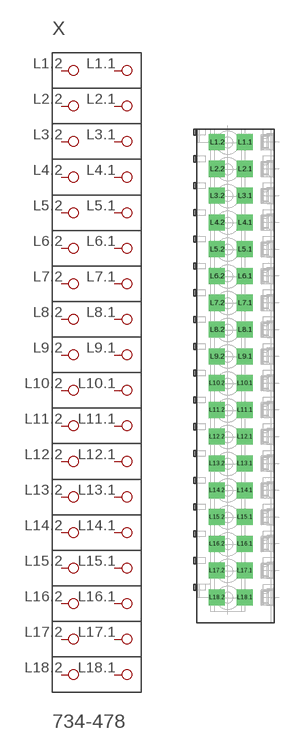
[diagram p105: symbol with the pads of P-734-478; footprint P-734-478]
Designator prefix X

## 734-478  [P-734-478]
L1.1  P1.1
L1.2  P1.2
L2.1  P2.1
L2.2  P2.2
L3.1  P3.1
L3.2  P3.2
L4.1  P4.1
L4.2  P4.2
L5.1  P5.1
L5.2  P5.2
L6.1  P6.1
L6.2  P6.2
L7.1  P7.1
L7.2  P7.2
L8.1  P8.1
L8.2  P8.2
L9.1  P9.1
L9.2  P9.2
L10.1  P10.1
L10.2  P10.2
L11.1  P11.1
L11.2  P11.2
L12.1  P12.1
L12.2  P12.2
L13.1  P13.1
L13.2  P13.2
L14.1  P14.1
L14.2  P14.2
L15.1  P15.1
L15.2  P15.2
L16.1  P16.1
L16.2  P16.2
L17.1  P17.1
L17.2  P17.2
L18.1  P18.1
L18.2  P18.2

## Footprint P-734-478 (pad centres in mm)
drill 1.4 square: L1.1 1.067,30.342; L1.2 -2.583,30.342; L2.1 1.067,26.842; L2.2 -2.583,26.842; L3.1 1.067,23.342; L3.2 -2.583,23.342; L4.1 1.067,19.842; L4.2 -2.583,19.842; L5.1 1.067,16.342; L5.2 -2.583,16.342; L6.1 1.067,12.842; L6.2 -2.583,12.842; L7.1 1.067,9.342; L7.2 -2.583,9.342; L8.1 1.067,5.842; L8.2 -2.583,5.842; L9.1 1.067,2.342; L9.2 -2.583,2.342; L10.1 1.067,-1.158; L10.2 -2.583,-1.158; L11.1 1.067,-4.658; L11.2 -2.583,-4.658; L12.1 1.067,-8.158; L12.2 -2.583,-8.158; L13.1 1.067,-11.658; L13.2 -2.583,-11.658; L14.1 1.067,-15.158; L14.2 -2.583,-15.158; L15.1 1.067,-18.658; L15.2 -2.583,-18.658; L16.1 1.067,-22.158; L16.2 -2.583,-22.158; L17.1 1.067,-25.658; L17.2 -2.583,-25.658; L18.1 1.067,-29.158; L18.2 -2.583,-29.158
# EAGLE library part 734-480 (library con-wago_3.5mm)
Serie 734, Federleiste mit geraden Einlötstiften / Series 734, Female connector with straight solder pins Polzahl / Pole No.: 20 Bemessungsspannung / Rated Voltage: 160 V Nennstrom / Nominal Current: 10 A Lötstiftlänge: / Solder Pin Length: 3.8 mm Farbe / Color: lichtgrau / light gray Stand: 01.01.2012. Die jeweils aktuellen Daten zu diesem Artikel finden Sie in unserem Produktkatalog, den Sie unter www.wago.com einsehen können. As of: 01/01/2012. Please find the newest data for this article in our product catalogue, which can be viewed under www.wago.com.

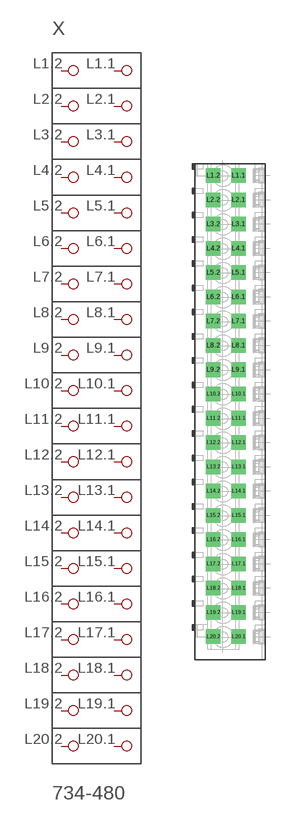
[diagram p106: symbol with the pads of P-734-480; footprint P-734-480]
Designator prefix X

## 734-480  [P-734-480]
L1.1  P1.1
L1.2  P1.2
L2.1  P2.1
L2.2  P2.2
L3.1  P3.1
L3.2  P3.2
L4.1  P4.1
L4.2  P4.2
L5.1  P5.1
L5.2  P5.2
L6.1  P6.1
L6.2  P6.2
L7.1  P7.1
L7.2  P7.2
L8.1  P8.1
L8.2  P8.2
L9.1  P9.1
L9.2  P9.2
L10.1  P10.1
L10.2  P10.2
L11.1  P11.1
L11.2  P11.2
L12.1  P12.1
L12.2  P12.2
L13.1  P13.1
L13.2  P13.2
L14.1  P14.1
L14.2  P14.2
L15.1  P15.1
L15.2  P15.2
L16.1  P16.1
L16.2  P16.2
L17.1  P17.1
L17.2  P17.2
L18.1  P18.1
L18.2  P18.2
L19.1  P19.1
L19.2  P19.2
L20.1  P20.1
L20.2  P20.2

## Footprint P-734-480 (pad centres in mm)
drill 1.4 square: L1.1 1.033,33.808; L1.2 -2.617,33.808; L2.1 1.033,30.308; L2.2 -2.617,30.308; L3.1 1.033,26.808; L3.2 -2.617,26.808; L4.1 1.033,23.308; L4.2 -2.617,23.308; L5.1 1.033,19.808; L5.2 -2.617,19.808; L6.1 1.033,16.308; L6.2 -2.617,16.308; L7.1 1.033,12.808; L7.2 -2.617,12.808; L8.1 1.033,9.308; L8.2 -2.617,9.308; L9.1 1.033,5.808; L9.2 -2.617,5.808; L10.1 1.033,2.308; L10.2 -2.617,2.308; L11.1 1.033,-1.192; L11.2 -2.617,-1.192; L12.1 1.033,-4.692; L12.2 -2.617,-4.692; L13.1 1.033,-8.192; L13.2 -2.617,-8.192; L14.1 1.033,-11.692; L14.2 -2.617,-11.692; L15.1 1.033,-15.192; L15.2 -2.617,-15.192; L16.1 1.033,-18.692; L16.2 -2.617,-18.692; L17.1 1.033,-22.192; L17.2 -2.617,-22.192; L18.1 1.033,-25.692; L18.2 -2.617,-25.692; L19.1 1.033,-29.192; L19.2 -2.617,-29.192; L20.1 1.033,-32.692; L20.2 -2.617,-32.692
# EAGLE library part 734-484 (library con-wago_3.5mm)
Serie 734, Federleiste mit geraden Einlötstiften / Series 734, Female connector with straight solder pins Polzahl / Pole No.: 24 Bemessungsspannung / Rated Voltage: 160 V Nennstrom / Nominal Current: 10 A Lötstiftlänge: / Solder Pin Length: 3.8 mm Farbe / Color: lichtgrau / light gray Stand: 01.01.2012. Die jeweils aktuellen Daten zu diesem Artikel finden Sie in unserem Produktkatalog, den Sie unter www.wago.com einsehen können. As of: 01/01/2012. Please find the newest data for this article in our product catalogue, which can be viewed under www.wago.com.

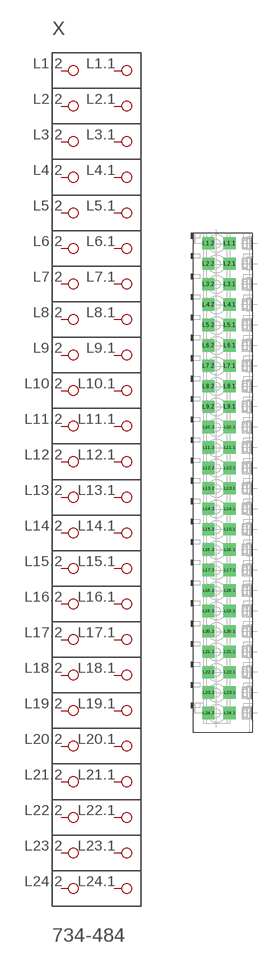
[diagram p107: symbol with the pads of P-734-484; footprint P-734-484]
Designator prefix X

## 734-484  [P-734-484]
L1.1  P1.1
L1.2  P1.2
L2.1  P2.1
L2.2  P2.2
L3.1  P3.1
L3.2  P3.2
L4.1  P4.1
L4.2  P4.2
L5.1  P5.1
L5.2  P5.2
L6.1  P6.1
L6.2  P6.2
L7.1  P7.1
L7.2  P7.2
L8.1  P8.1
L8.2  P8.2
L9.1  P9.1
L9.2  P9.2
L10.1  P10.1
L10.2  P10.2
L11.1  P11.1
L11.2  P11.2
L12.1  P12.1
L12.2  P12.2
L13.1  P13.1
L13.2  P13.2
L14.1  P14.1
L14.2  P14.2
L15.1  P15.1
L15.2  P15.2
L16.1  P16.1
L16.2  P16.2
L17.1  P17.1
L17.2  P17.2
L18.1  P18.1
L18.2  P18.2
L19.1  P19.1
L19.2  P19.2
L20.1  P20.1
L20.2  P20.2
L21.1  P21.1
L21.2  P21.2
L22.1  P22.1
L22.2  P22.2
L23.1  P23.1
L23.2  P23.2
L24.1  P24.1
L24.2  P24.2

## Footprint P-734-484 (pad centres in mm)
drill 1.4 square: L1.1 0.964,40.739; L1.2 -2.687,40.739; L2.1 0.964,37.239; L2.2 -2.687,37.239; L3.1 0.964,33.739; L3.2 -2.687,33.739; L4.1 0.964,30.238; L4.2 -2.687,30.238; L5.1 0.964,26.738; L5.2 -2.687,26.738; L6.1 0.964,23.238; L6.2 -2.687,23.238; L7.1 0.964,19.738; L7.2 -2.687,19.738; L8.1 0.964,16.238; L8.2 -2.687,16.238; L9.1 0.964,12.739; L9.2 -2.687,12.739; L10.1 0.964,9.239; L10.2 -2.687,9.239; L11.1 0.964,5.739; L11.2 -2.687,5.739; L12.1 0.964,2.239; L12.2 -2.687,2.239; L13.1 0.964,-1.262; L13.2 -2.687,-1.262; L14.1 0.964,-4.761; L14.2 -2.687,-4.761; L15.1 0.964,-8.261; L15.2 -2.687,-8.261; L16.1 0.964,-11.761; L16.2 -2.687,-11.761; L17.1 0.964,-15.261; L17.2 -2.687,-15.261; L18.1 0.964,-18.762; L18.2 -2.687,-18.762; L19.1 0.964,-22.262; L19.2 -2.687,-22.262; L20.1 0.964,-25.762; L20.2 -2.687,-25.762; L21.1 0.964,-29.262; L21.2 -2.687,-29.262; L22.1 0.964,-32.761; L22.2 -2.687,-32.761; L23.1 0.964,-36.261; L23.2 -2.687,-36.261; L24.1 0.964,-39.761; L24.2 -2.687,-39.761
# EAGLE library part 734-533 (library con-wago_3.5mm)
Serie 734, Federleiste mit abgewinkelten Einlötstiften / Series 734, Female connector with angled solder pins Polzahl / Pole No.: 3 Bemessungsspannung / Rated Voltage: 160 V Nennstrom / Nominal Current: 10 A Lötstiftlänge: / Solder Pin Length: 3.8 mm Farbe / Color: lichtgrau / light gray Stand: 01.01.2012. Die jeweils aktuellen Daten zu diesem Artikel finden Sie in unserem Produktkatalog, den Sie unter www.wago.com einsehen können. As of: 01/01/2012. Please find the newest data for this article in our product catalogue, which can be viewed under www.wago.com.

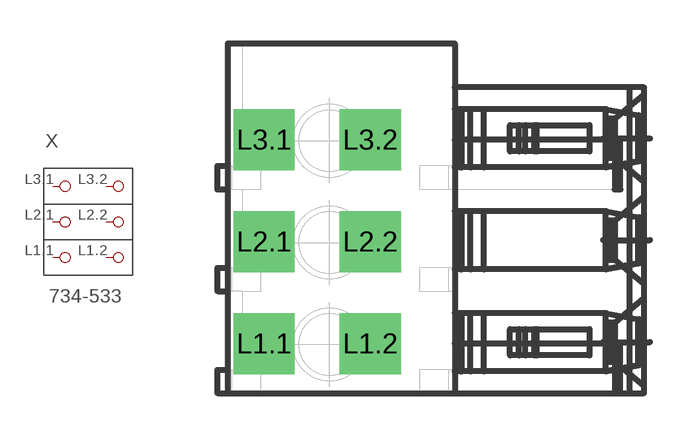
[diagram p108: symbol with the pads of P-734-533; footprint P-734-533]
Designator prefix X

## 734-533  [P-734-533]
L1.1  P1.1
L1.2  P1.2
L2.1  P2.1
L2.2  P2.2
L3.1  P3.1
L3.2  P3.2

## Footprint P-734-533 (pad centres in mm)
drill 1.4 square: L1.1 -5.829,-4.3; L1.2 -2.179,-4.3; L2.1 -5.829,-0.8; L2.2 -2.179,-0.8; L3.1 -5.829,2.7; L3.2 -2.179,2.7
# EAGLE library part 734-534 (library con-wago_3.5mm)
Serie 734, Federleiste mit abgewinkelten Einlötstiften / Series 734, Female connector with angled solder pins Polzahl / Pole No.: 4 Bemessungsspannung / Rated Voltage: 160 V Nennstrom / Nominal Current: 10 A Lötstiftlänge: / Solder Pin Length: 3.8 mm Farbe / Color: lichtgrau / light gray Stand: 01.01.2012. Die jeweils aktuellen Daten zu diesem Artikel finden Sie in unserem Produktkatalog, den Sie unter www.wago.com einsehen können. As of: 01/01/2012. Please find the newest data for this article in our product catalogue, which can be viewed under www.wago.com.

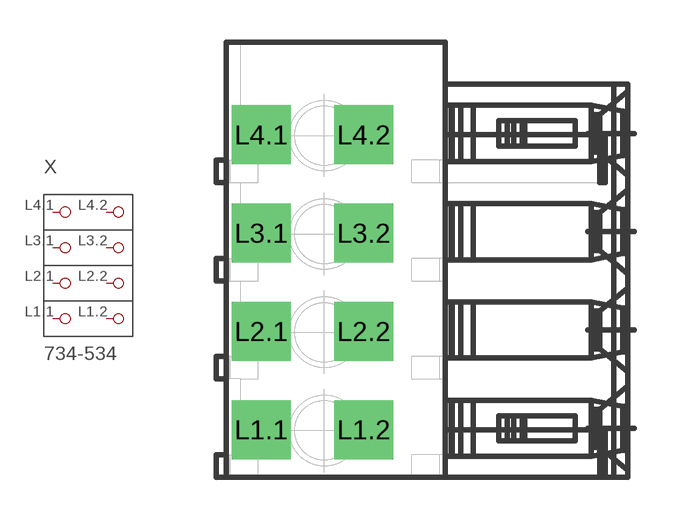
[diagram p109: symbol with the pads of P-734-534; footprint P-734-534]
Designator prefix X

## 734-534  [P-734-534]
L1.1  P1.1
L1.2  P1.2
L2.1  P2.1
L2.2  P2.2
L3.1  P3.1
L3.2  P3.2
L4.1  P4.1
L4.2  P4.2

## Footprint P-734-534 (pad centres in mm)
drill 1.4 square: L1.1 -5.84,-6.05; L1.2 -2.191,-6.05; L2.1 -5.84,-2.55; L2.2 -2.191,-2.55; L3.1 -5.84,0.95; L3.2 -2.191,0.95; L4.1 -5.84,4.45; L4.2 -2.191,4.45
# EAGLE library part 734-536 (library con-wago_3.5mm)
Serie 734, Federleiste mit abgewinkelten Einlötstiften / Series 734, Female connector with angled solder pins Polzahl / Pole No.: 6 Bemessungsspannung / Rated Voltage: 160 V Nennstrom / Nominal Current: 10 A Lötstiftlänge: / Solder Pin Length: 3.8 mm Farbe / Color: lichtgrau / light gray Stand: 01.01.2012. Die jeweils aktuellen Daten zu diesem Artikel finden Sie in unserem Produktkatalog, den Sie unter www.wago.com einsehen können. As of: 01/01/2012. Please find the newest data for this article in our product catalogue, which can be viewed under www.wago.com.

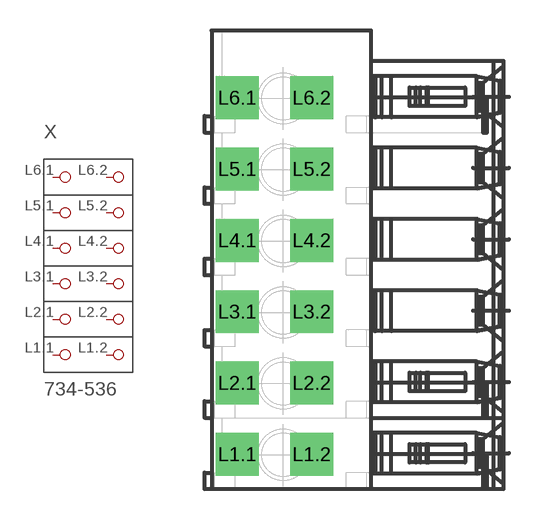
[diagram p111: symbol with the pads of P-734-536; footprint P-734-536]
Designator prefix X

## 734-536  [P-734-536]
L1.1  P1.1
L1.2  P1.2
L2.1  P2.1
L2.2  P2.2
L3.1  P3.1
L3.2  P3.2
L4.1  P4.1
L4.2  P4.2
L5.1  P5.1
L5.2  P5.2
L6.1  P6.1
L6.2  P6.2

## Footprint P-734-536 (pad centres in mm)
drill 1.4 square: L1.1 -5.868,-9.55; L1.2 -2.218,-9.55; L2.1 -5.868,-6.05; L2.2 -2.218,-6.05; L3.1 -5.868,-2.55; L3.2 -2.218,-2.55; L4.1 -5.868,0.95; L4.2 -2.218,0.95; L5.1 -5.868,4.45; L5.2 -2.218,4.45; L6.1 -5.868,7.95; L6.2 -2.218,7.95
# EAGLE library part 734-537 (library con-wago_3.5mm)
Serie 734, Federleiste mit abgewinkelten Einlötstiften / Series 734, Female connector with angled solder pins Polzahl / Pole No.: 7 Bemessungsspannung / Rated Voltage: 160 V Nennstrom / Nominal Current: 10 A Lötstiftlänge: / Solder Pin Length: 3.8 mm Farbe / Color: lichtgrau / light gray Stand: 01.01.2012. Die jeweils aktuellen Daten zu diesem Artikel finden Sie in unserem Produktkatalog, den Sie unter www.wago.com einsehen können. As of: 01/01/2012. Please find the newest data for this article in our product catalogue, which can be viewed under www.wago.com.

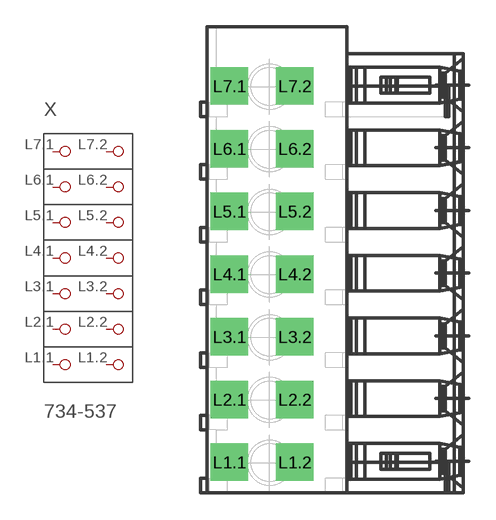
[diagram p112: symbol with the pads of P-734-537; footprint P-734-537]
Designator prefix X

## 734-537  [P-734-537]
L1.1  P1.1
L1.2  P1.2
L2.1  P2.1
L2.2  P2.2
L3.1  P3.1
L3.2  P3.2
L4.1  P4.1
L4.2  P4.2
L5.1  P5.1
L5.2  P5.2
L6.1  P6.1
L6.2  P6.2
L7.1  P7.1
L7.2  P7.2

## Footprint P-734-537 (pad centres in mm)
drill 1.4 square: L1.1 -5.882,-11.3; L1.2 -2.232,-11.3; L2.1 -5.882,-7.8; L2.2 -2.232,-7.8; L3.1 -5.882,-4.3; L3.2 -2.232,-4.3; L4.1 -5.882,-0.8; L4.2 -2.232,-0.8; L5.1 -5.882,2.7; L5.2 -2.232,2.7; L6.1 -5.882,6.2; L6.2 -2.232,6.2; L7.1 -5.882,9.7; L7.2 -2.232,9.7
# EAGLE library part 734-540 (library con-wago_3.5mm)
Serie 734, Federleiste mit abgewinkelten Einlötstiften / Series 734, Female connector with angled solder pins Polzahl / Pole No.: 10 Bemessungsspannung / Rated Voltage: 160 V Nennstrom / Nominal Current: 10 A Lötstiftlänge: / Solder Pin Length: 3.8 mm Farbe / Color: lichtgrau / light gray Stand: 01.01.2012. Die jeweils aktuellen Daten zu diesem Artikel finden Sie in unserem Produktkatalog, den Sie unter www.wago.com einsehen können. As of: 01/01/2012. Please find the newest data for this article in our product catalogue, which can be viewed under www.wago.com.

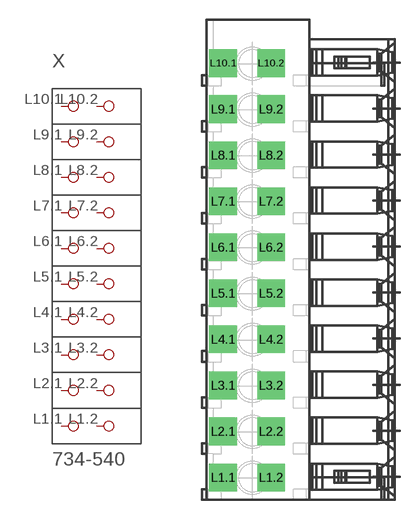
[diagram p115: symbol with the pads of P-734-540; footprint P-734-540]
Designator prefix X

## 734-540  [P-734-540]
L1.1  P1.1
L1.2  P1.2
L2.1  P2.1
L2.2  P2.2
L3.1  P3.1
L3.2  P3.2
L4.1  P4.1
L4.2  P4.2
L5.1  P5.1
L5.2  P5.2
L6.1  P6.1
L6.2  P6.2
L7.1  P7.1
L7.2  P7.2
L8.1  P8.1
L8.2  P8.2
L9.1  P9.1
L9.2  P9.2
L10.1  P10.1
L10.2  P10.2

## Footprint P-734-540 (pad centres in mm)
drill 1.4 square: L1.1 -5.929,-16.55; L1.2 -2.279,-16.55; L2.1 -5.929,-13.05; L2.2 -2.279,-13.05; L3.1 -5.929,-9.55; L3.2 -2.279,-9.55; L4.1 -5.929,-6.05; L4.2 -2.279,-6.05; L5.1 -5.929,-2.55; L5.2 -2.279,-2.55; L6.1 -5.929,0.95; L6.2 -2.279,0.95; L7.1 -5.929,4.45; L7.2 -2.279,4.45; L8.1 -5.929,7.95; L8.2 -2.279,7.95; L9.1 -5.929,11.45; L9.2 -2.279,11.45; L10.1 -5.929,14.95; L10.2 -2.279,14.95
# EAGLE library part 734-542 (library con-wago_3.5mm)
Serie 734, Federleiste mit abgewinkelten Einlötstiften / Series 734, Female connector with angled solder pins Polzahl / Pole No.: 12 Bemessungsspannung / Rated Voltage: 160 V Nennstrom / Nominal Current: 10 A Lötstiftlänge: / Solder Pin Length: 3.8 mm Farbe / Color: lichtgrau / light gray Stand: 01.01.2012. Die jeweils aktuellen Daten zu diesem Artikel finden Sie in unserem Produktkatalog, den Sie unter www.wago.com einsehen können. As of: 01/01/2012. Please find the newest data for this article in our product catalogue, which can be viewed under www.wago.com.

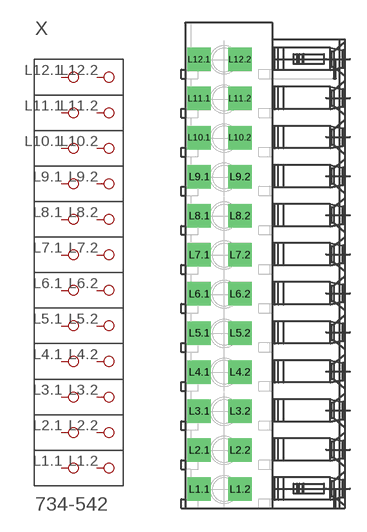
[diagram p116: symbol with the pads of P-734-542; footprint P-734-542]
Designator prefix X

## 734-542  [P-734-542]
L1.1  P1.1
L1.2  P1.2
L2.1  P2.1
L2.2  P2.2
L3.1  P3.1
L3.2  P3.2
L4.1  P4.1
L4.2  P4.2
L5.1  P5.1
L5.2  P5.2
L6.1  P6.1
L6.2  P6.2
L7.1  P7.1
L7.2  P7.2
L8.1  P8.1
L8.2  P8.2
L9.1  P9.1
L9.2  P9.2
L10.1  P10.1
L10.2  P10.2
L11.1  P11.1
L11.2  P11.2
L12.1  P12.1
L12.2  P12.2

## Footprint P-734-542 (pad centres in mm)
drill 1.4 square: L1.1 -5.962,-20.023; L1.2 -2.312,-20.023; L2.1 -5.962,-16.523; L2.2 -2.312,-16.523; L3.1 -5.962,-13.023; L3.2 -2.312,-13.023; L4.1 -5.962,-9.523; L4.2 -2.312,-9.523; L5.1 -5.962,-6.023; L5.2 -2.312,-6.023; L6.1 -5.962,-2.523; L6.2 -2.312,-2.523; L7.1 -5.962,0.977; L7.2 -2.312,0.977; L8.1 -5.962,4.477; L8.2 -2.312,4.477; L9.1 -5.962,7.977; L9.2 -2.312,7.977; L10.1 -5.962,11.477; L10.2 -2.312,11.477; L11.1 -5.962,14.977; L11.2 -2.312,14.977; L12.1 -5.962,18.477; L12.2 -2.312,18.477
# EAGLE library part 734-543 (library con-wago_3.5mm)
Serie 734, Federleiste mit abgewinkelten Einlötstiften / Series 734, Female connector with angled solder pins Polzahl / Pole No.: 13 Bemessungsspannung / Rated Voltage: 160 V Nennstrom / Nominal Current: 10 A Lötstiftlänge: / Solder Pin Length: 3.8 mm Farbe / Color: lichtgrau / light gray Stand: 01.01.2012. Die jeweils aktuellen Daten zu diesem Artikel finden Sie in unserem Produktkatalog, den Sie unter www.wago.com einsehen können. As of: 01/01/2012. Please find the newest data for this article in our product catalogue, which can be viewed under www.wago.com.

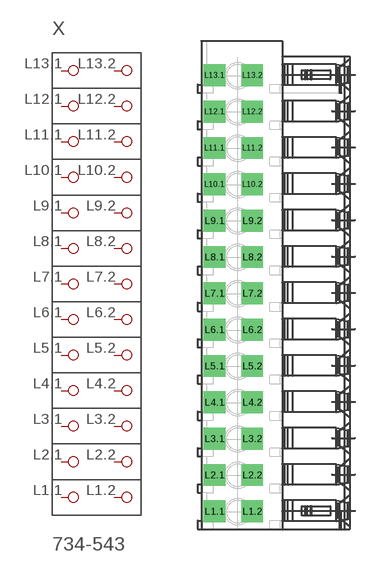
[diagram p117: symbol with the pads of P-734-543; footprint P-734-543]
Designator prefix X

## 734-543  [P-734-543]
L1.1  P1.1
L1.2  P1.2
L2.1  P2.1
L2.2  P2.2
L3.1  P3.1
L3.2  P3.2
L4.1  P4.1
L4.2  P4.2
L5.1  P5.1
L5.2  P5.2
L6.1  P6.1
L6.2  P6.2
L7.1  P7.1
L7.2  P7.2
L8.1  P8.1
L8.2  P8.2
L9.1  P9.1
L9.2  P9.2
L10.1  P10.1
L10.2  P10.2
L11.1  P11.1
L11.2  P11.2
L12.1  P12.1
L12.2  P12.2
L13.1  P13.1
L13.2  P13.2

## Footprint P-734-543 (pad centres in mm)
drill 1.4 square: L1.1 -5.978,-21.757; L1.2 -2.328,-21.757; L2.1 -5.978,-18.257; L2.2 -2.328,-18.257; L3.1 -5.978,-14.757; L3.2 -2.328,-14.757; L4.1 -5.978,-11.257; L4.2 -2.328,-11.257; L5.1 -5.978,-7.757; L5.2 -2.328,-7.757; L6.1 -5.978,-4.257; L6.2 -2.328,-4.257; L7.1 -5.978,-0.757; L7.2 -2.328,-0.757; L8.1 -5.978,2.743; L8.2 -2.328,2.743; L9.1 -5.978,6.243; L9.2 -2.328,6.243; L10.1 -5.978,9.743; L10.2 -2.328,9.743; L11.1 -5.978,13.243; L11.2 -2.328,13.243; L12.1 -5.978,16.743; L12.2 -2.328,16.743; L13.1 -5.978,20.243; L13.2 -2.328,20.243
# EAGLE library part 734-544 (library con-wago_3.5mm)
Serie 734, Federleiste mit abgewinkelten Einlötstiften / Series 734, Female connector with angled solder pins Polzahl / Pole No.: 14 Bemessungsspannung / Rated Voltage: 160 V Nennstrom / Nominal Current: 10 A Lötstiftlänge: / Solder Pin Length: 3.8 mm Farbe / Color: lichtgrau / light gray Stand: 01.01.2012. Die jeweils aktuellen Daten zu diesem Artikel finden Sie in unserem Produktkatalog, den Sie unter www.wago.com einsehen können. As of: 01/01/2012. Please find the newest data for this article in our product catalogue, which can be viewed under www.wago.com.

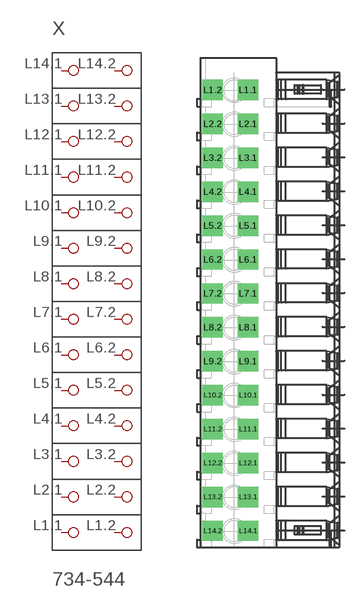
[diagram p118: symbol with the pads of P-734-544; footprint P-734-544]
Designator prefix X

## 734-544  [P-734-544]
L1.1  P1.1
L1.2  P1.2
L2.1  P2.1
L2.2  P2.2
L3.1  P3.1
L3.2  P3.2
L4.1  P4.1
L4.2  P4.2
L5.1  P5.1
L5.2  P5.2
L6.1  P6.1
L6.2  P6.2
L7.1  P7.1
L7.2  P7.2
L8.1  P8.1
L8.2  P8.2
L9.1  P9.1
L9.2  P9.2
L10.1  P10.1
L10.2  P10.2
L11.1  P11.1
L11.2  P11.2
L12.1  P12.1
L12.2  P12.2
L13.1  P13.1
L13.2  P13.2
L14.1  P14.1
L14.2  P14.2

## Footprint P-734-544 (pad centres in mm)
drill 1.4 square: L1.1 -2.345,22.01; L1.2 -5.995,22.01; L2.1 -2.345,18.51; L2.2 -5.995,18.51; L3.1 -2.345,15.01; L3.2 -5.995,15.01; L4.1 -2.345,11.51; L4.2 -5.995,11.51; L5.1 -2.345,8.01; L5.2 -5.995,8.01; L6.1 -2.345,4.51; L6.2 -5.995,4.51; L7.1 -2.345,1.01; L7.2 -5.995,1.01; L8.1 -2.345,-2.49; L8.2 -5.995,-2.49; L9.1 -2.345,-5.99; L9.2 -5.995,-5.99; L10.1 -2.345,-9.49; L10.2 -5.995,-9.49; L11.1 -2.345,-12.99; L11.2 -5.995,-12.99; L12.1 -2.345,-16.49; L12.2 -5.995,-16.49; L13.1 -2.345,-19.99; L13.2 -5.995,-19.99; L14.1 -2.345,-23.49; L14.2 -5.995,-23.49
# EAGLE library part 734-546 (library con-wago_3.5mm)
Serie 734, Federleiste mit abgewinkelten Einlötstiften / Series 734, Female connector with angled solder pins Polzahl / Pole No.: 16 Bemessungsspannung / Rated Voltage: 160 V Nennstrom / Nominal Current: 10 A Lötstiftlänge: / Solder Pin Length: 3.8 mm Farbe / Color: lichtgrau / light gray Stand: 01.01.2012. Die jeweils aktuellen Daten zu diesem Artikel finden Sie in unserem Produktkatalog, den Sie unter www.wago.com einsehen können. As of: 01/01/2012. Please find the newest data for this article in our product catalogue, which can be viewed under www.wago.com.

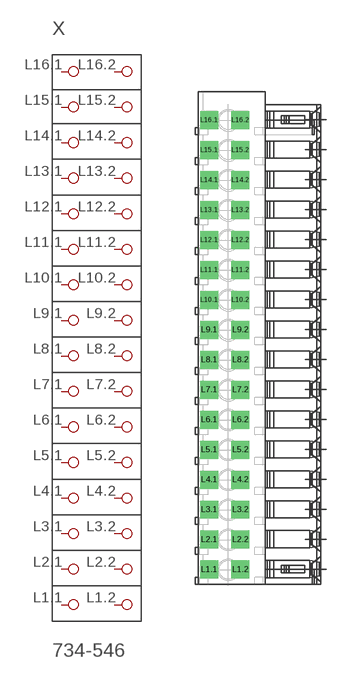
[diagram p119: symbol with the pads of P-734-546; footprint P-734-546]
Designator prefix X

## 734-546  [P-734-546]
L1.1  P1.1
L1.2  P1.2
L2.1  P2.1
L2.2  P2.2
L3.1  P3.1
L3.2  P3.2
L4.1  P4.1
L4.2  P4.2
L5.1  P5.1
L5.2  P5.2
L6.1  P6.1
L6.2  P6.2
L7.1  P7.1
L7.2  P7.2
L8.1  P8.1
L8.2  P8.2
L9.1  P9.1
L9.2  P9.2
L10.1  P10.1
L10.2  P10.2
L11.1  P11.1
L11.2  P11.2
L12.1  P12.1
L12.2  P12.2
L13.1  P13.1
L13.2  P13.2
L14.1  P14.1
L14.2  P14.2
L15.1  P15.1
L15.2  P15.2
L16.1  P16.1
L16.2  P16.2

## Footprint P-734-546 (pad centres in mm)
drill 1.4 square: L1.1 -6.028,-26.957; L1.2 -2.378,-26.957; L2.1 -6.028,-23.457; L2.2 -2.378,-23.457; L3.1 -6.028,-19.957; L3.2 -2.378,-19.957; L4.1 -6.028,-16.457; L4.2 -2.378,-16.457; L5.1 -6.028,-12.957; L5.2 -2.378,-12.957; L6.1 -6.028,-9.457; L6.2 -2.378,-9.457; L7.1 -6.028,-5.957; L7.2 -2.378,-5.957; L8.1 -6.028,-2.457; L8.2 -2.378,-2.457; L9.1 -6.028,1.043; L9.2 -2.378,1.043; L10.1 -6.028,4.543; L10.2 -2.378,4.543; L11.1 -6.028,8.043; L11.2 -2.378,8.043; L12.1 -6.028,11.543; L12.2 -2.378,11.543; L13.1 -6.028,15.043; L13.2 -2.378,15.043; L14.1 -6.028,18.543; L14.2 -2.378,18.543; L15.1 -6.028,22.043; L15.2 -2.378,22.043; L16.1 -6.028,25.543; L16.2 -2.378,25.543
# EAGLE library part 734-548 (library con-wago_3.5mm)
Serie 734, Federleiste mit abgewinkelten Einlötstiften / Series 734, Female connector with angled solder pins Polzahl / Pole No.: 18 Bemessungsspannung / Rated Voltage: 160 V Nennstrom / Nominal Current: 10 A Lötstiftlänge: / Solder Pin Length: 3.8 mm Farbe / Color: lichtgrau / light gray Stand: 01.01.2012. Die jeweils aktuellen Daten zu diesem Artikel finden Sie in unserem Produktkatalog, den Sie unter www.wago.com einsehen können. As of: 01/01/2012. Please find the newest data for this article in our product catalogue, which can be viewed under www.wago.com.

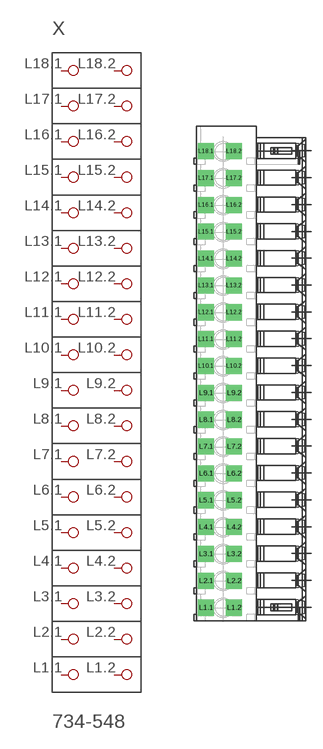
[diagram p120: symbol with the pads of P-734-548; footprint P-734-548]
Designator prefix X

## 734-548  [P-734-548]
L1.1  P1.1
L1.2  P1.2
L2.1  P2.1
L2.2  P2.2
L3.1  P3.1
L3.2  P3.2
L4.1  P4.1
L4.2  P4.2
L5.1  P5.1
L5.2  P5.2
L6.1  P6.1
L6.2  P6.2
L7.1  P7.1
L7.2  P7.2
L8.1  P8.1
L8.2  P8.2
L9.1  P9.1
L9.2  P9.2
L10.1  P10.1
L10.2  P10.2
L11.1  P11.1
L11.2  P11.2
L12.1  P12.1
L12.2  P12.2
L13.1  P13.1
L13.2  P13.2
L14.1  P14.1
L14.2  P14.2
L15.1  P15.1
L15.2  P15.2
L16.1  P16.1
L16.2  P16.2
L17.1  P17.1
L17.2  P17.2
L18.1  P18.1
L18.2  P18.2

## Footprint P-734-548 (pad centres in mm)
drill 1.4 square: L1.1 -6.062,-30.423; L1.2 -2.412,-30.423; L2.1 -6.062,-26.923; L2.2 -2.412,-26.923; L3.1 -6.062,-23.423; L3.2 -2.412,-23.423; L4.1 -6.062,-19.923; L4.2 -2.412,-19.923; L5.1 -6.062,-16.423; L5.2 -2.412,-16.423; L6.1 -6.062,-12.923; L6.2 -2.412,-12.923; L7.1 -6.062,-9.423; L7.2 -2.412,-9.423; L8.1 -6.062,-5.923; L8.2 -2.412,-5.923; L9.1 -6.062,-2.423; L9.2 -2.412,-2.423; L10.1 -6.062,1.077; L10.2 -2.412,1.077; L11.1 -6.062,4.577; L11.2 -2.412,4.577; L12.1 -6.062,8.077; L12.2 -2.412,8.077; L13.1 -6.062,11.577; L13.2 -2.412,11.577; L14.1 -6.062,15.077; L14.2 -2.412,15.077; L15.1 -6.062,18.577; L15.2 -2.412,18.577; L16.1 -6.062,22.077; L16.2 -2.412,22.077; L17.1 -6.062,25.577; L17.2 -2.412,25.577; L18.1 -6.062,29.077; L18.2 -2.412,29.077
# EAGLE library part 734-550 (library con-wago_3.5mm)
Serie 734, Federleiste mit abgewinkelten Einlötstiften / Series 734, Female connector with angled solder pins Polzahl / Pole No.: 20 Bemessungsspannung / Rated Voltage: 160 V Nennstrom / Nominal Current: 10 A Lötstiftlänge: / Solder Pin Length: 3.8 mm Farbe / Color: lichtgrau / light gray Stand: 01.01.2012. Die jeweils aktuellen Daten zu diesem Artikel finden Sie in unserem Produktkatalog, den Sie unter www.wago.com einsehen können. As of: 01/01/2012. Please find the newest data for this article in our product catalogue, which can be viewed under www.wago.com.

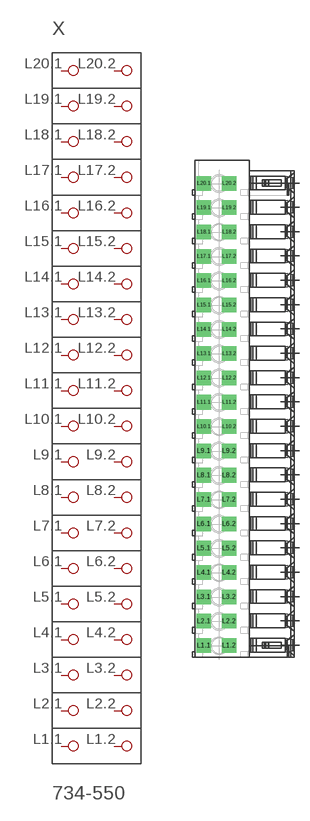
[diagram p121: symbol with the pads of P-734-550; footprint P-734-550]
Designator prefix X

## 734-550  [P-734-550]
L1.1  P1.1
L1.2  P1.2
L2.1  P2.1
L2.2  P2.2
L3.1  P3.1
L3.2  P3.2
L4.1  P4.1
L4.2  P4.2
L5.1  P5.1
L5.2  P5.2
L6.1  P6.1
L6.2  P6.2
L7.1  P7.1
L7.2  P7.2
L8.1  P8.1
L8.2  P8.2
L9.1  P9.1
L9.2  P9.2
L10.1  P10.1
L10.2  P10.2
L11.1  P11.1
L11.2  P11.2
L12.1  P12.1
L12.2  P12.2
L13.1  P13.1
L13.2  P13.2
L14.1  P14.1
L14.2  P14.2
L15.1  P15.1
L15.2  P15.2
L16.1  P16.1
L16.2  P16.2
L17.1  P17.1
L17.2  P17.2
L18.1  P18.1
L18.2  P18.2
L19.1  P19.1
L19.2  P19.2
L20.1  P20.1
L20.2  P20.2

## Footprint P-734-550 (pad centres in mm)
drill 1.4 square: L1.1 -6.096,-33.889; L1.2 -2.446,-33.889; L2.1 -6.096,-30.389; L2.2 -2.446,-30.389; L3.1 -6.096,-26.889; L3.2 -2.446,-26.889; L4.1 -6.096,-23.389; L4.2 -2.446,-23.389; L5.1 -6.096,-19.889; L5.2 -2.446,-19.889; L6.1 -6.096,-16.389; L6.2 -2.446,-16.389; L7.1 -6.096,-12.889; L7.2 -2.446,-12.889; L8.1 -6.096,-9.389; L8.2 -2.446,-9.389; L9.1 -6.096,-5.889; L9.2 -2.446,-5.889; L10.1 -6.096,-2.389; L10.2 -2.446,-2.389; L11.1 -6.096,1.111; L11.2 -2.446,1.111; L12.1 -6.096,4.611; L12.2 -2.446,4.611; L13.1 -6.096,8.111; L13.2 -2.446,8.111; L14.1 -6.096,11.611; L14.2 -2.446,11.611; L15.1 -6.096,15.111; L15.2 -2.446,15.111; L16.1 -6.096,18.611; L16.2 -2.446,18.611; L17.1 -6.096,22.111; L17.2 -2.446,22.111; L18.1 -6.096,25.611; L18.2 -2.446,25.611; L19.1 -6.096,29.111; L19.2 -2.446,29.111; L20.1 -6.096,32.611; L20.2 -2.446,32.611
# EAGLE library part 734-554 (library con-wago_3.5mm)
Serie 734, Federleiste mit abgewinkelten Einlötstiften / Series 734, Female connector with angled solder pins Polzahl / Pole No.: 24 Bemessungsspannung / Rated Voltage: 160 V Nennstrom / Nominal Current: 10 A Lötstiftlänge: / Solder Pin Length: 3.8 mm Farbe / Color: lichtgrau / light gray Stand: 01.01.2012. Die jeweils aktuellen Daten zu diesem Artikel finden Sie in unserem Produktkatalog, den Sie unter www.wago.com einsehen können. As of: 01/01/2012. Please find the newest data for this article in our product catalogue, which can be viewed under www.wago.com.

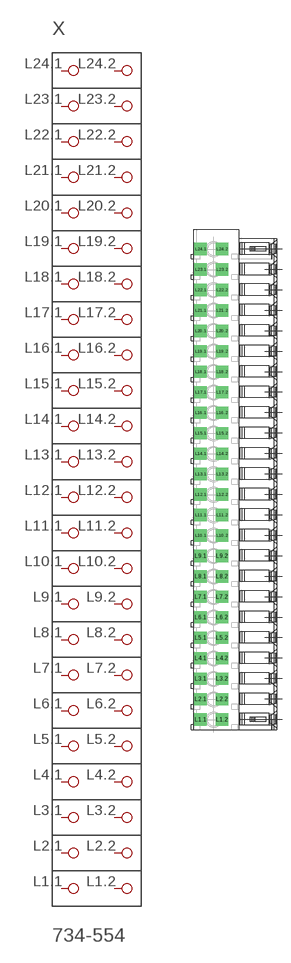
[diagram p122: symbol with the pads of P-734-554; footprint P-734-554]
Designator prefix X

## 734-554  [P-734-554]
L1.1  P1.1
L1.2  P1.2
L2.1  P2.1
L2.2  P2.2
L3.1  P3.1
L3.2  P3.2
L4.1  P4.1
L4.2  P4.2
L5.1  P5.1
L5.2  P5.2
L6.1  P6.1
L6.2  P6.2
L7.1  P7.1
L7.2  P7.2
L8.1  P8.1
L8.2  P8.2
L9.1  P9.1
L9.2  P9.2
L10.1  P10.1
L10.2  P10.2
L11.1  P11.1
L11.2  P11.2
L12.1  P12.1
L12.2  P12.2
L13.1  P13.1
L13.2  P13.2
L14.1  P14.1
L14.2  P14.2
L15.1  P15.1
L15.2  P15.2
L16.1  P16.1
L16.2  P16.2
L17.1  P17.1
L17.2  P17.2
L18.1  P18.1
L18.2  P18.2
L19.1  P19.1
L19.2  P19.2
L20.1  P20.1
L20.2  P20.2
L21.1  P21.1
L21.2  P21.2
L22.1  P22.1
L22.2  P22.2
L23.1  P23.1
L23.2  P23.2
L24.1  P24.1
L24.2  P24.2

## Footprint P-734-554 (pad centres in mm)
drill 1.4 square: L1.1 -6.165,-40.82; L1.2 -2.515,-40.82; L2.1 -6.165,-37.32; L2.2 -2.515,-37.32; L3.1 -6.165,-33.82; L3.2 -2.515,-33.82; L4.1 -6.165,-30.32; L4.2 -2.515,-30.32; L5.1 -6.165,-26.82; L5.2 -2.515,-26.82; L6.1 -6.165,-23.32; L6.2 -2.515,-23.32; L7.1 -6.165,-19.82; L7.2 -2.515,-19.82; L8.1 -6.165,-16.32; L8.2 -2.515,-16.32; L9.1 -6.165,-12.82; L9.2 -2.515,-12.82; L10.1 -6.165,-9.32; L10.2 -2.515,-9.32; L11.1 -6.165,-5.82; L11.2 -2.515,-5.82; L12.1 -6.165,-2.32; L12.2 -2.515,-2.32; L13.1 -6.165,1.18; L13.2 -2.515,1.18; L14.1 -6.165,4.68; L14.2 -2.515,4.68; L15.1 -6.165,8.18; L15.2 -2.515,8.18; L16.1 -6.165,11.68; L16.2 -2.515,11.68; L17.1 -6.165,15.18; L17.2 -2.515,15.18; L18.1 -6.165,18.68; L18.2 -2.515,18.68; L19.1 -6.165,22.18; L19.2 -2.515,22.18; L20.1 -6.165,25.68; L20.2 -2.515,25.68; L21.1 -6.165,29.18; L21.2 -2.515,29.18; L22.1 -6.165,32.68; L22.2 -2.515,32.68; L23.1 -6.165,36.18; L23.2 -2.515,36.18; L24.1 -6.165,39.68; L24.2 -2.515,39.68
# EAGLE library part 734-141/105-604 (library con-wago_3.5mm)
Serie 734, Stiftleiste (für Leiterplatten) Einlötstift gerade 1 x 1 mm / Series 734, Male header (for PCBs) Straight solder pin 1 x 1 mm Polzahl / Pole No.: 11 Lötstiftlänge: / Solder Pin Length: 2.4 mm Farbe / Color: schwarz / black Stand: 01.01.2012. Die jeweils aktuellen Daten zu diesem Artikel finden Sie in unserem Produktkatalog, den Sie unter www.wago.com einsehen können. As of: 01/01/2012. Please find the newest data for this article in our product catalogue, which can be viewed under www.wago.com.

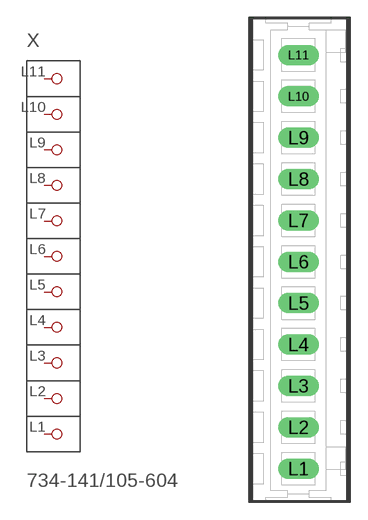
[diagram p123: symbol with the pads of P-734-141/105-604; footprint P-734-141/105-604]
Designator prefix X

## 734-141/105-604  [P-734-141/105-604]
L1  P1
L2  P2
L3  P3
L4  P4
L5  P5
L6  P6
L7  P7
L8  P8
L9  P9
L10  P10
L11  P11

## Footprint P-734-141/105-604 (pad centres in mm)
drill 1.15 long: L1 -0.1,-17.675; L2 -0.1,-14.175; L3 -0.1,-10.675; L4 -0.1,-7.175; L5 -0.1,-3.675; L6 -0.1,-0.175; L7 -0.1,3.325; L8 -0.1,6.825; L9 -0.1,10.325; L10 -0.1,13.825; L11 -0.1,17.325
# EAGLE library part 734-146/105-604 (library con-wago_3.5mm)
Serie 734, Stiftleiste (für Leiterplatten) Einlötstift gerade 1 x 1 mm / Series 734, Male header (for PCBs) Straight solder pin 1 x 1 mm Polzahl / Pole No.: 16 Bemessungsspannung / Rated Voltage: 160 V Nennstrom / Nominal Current: 10 A Lötstiftlänge: / Solder Pin Length: 2.4 mm Farbe / Color: schwarz / black Stand: 01.01.2012. Die jeweils aktuellen Daten zu diesem Artikel finden Sie in unserem Produktkatalog, den Sie unter www.wago.com einsehen können. As of: 01/01/2012. Please find the newest data for this article in our product catalogue, which can be viewed under www.wago.com.

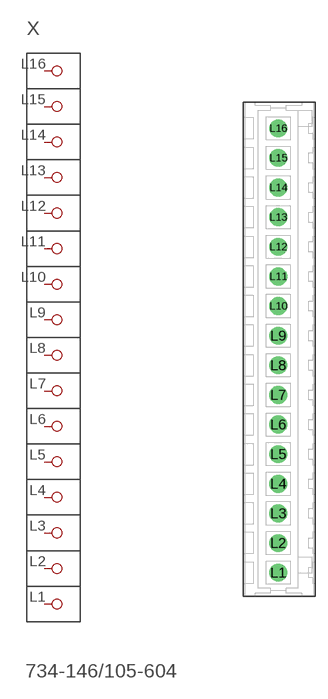
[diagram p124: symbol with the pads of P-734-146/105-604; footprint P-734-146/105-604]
Designator prefix X

## 734-146/105-604  [P-734-146/105-604]
L1  P1
L2  P2
L3  P3
L4  P4
L5  P5
L6  P6
L7  P7
L8  P8
L9  P9
L10  P10
L11  P11
L12  P12
L13  P13
L14  P14
L15  P15
L16  P16

## Footprint P-734-146/105-604 (pad centres in mm)
drill 1.4 round: L1 -0.1,-26.4; L2 -0.1,-22.9; L3 -0.1,-19.4; L4 -0.1,-15.9; L5 -0.1,-12.4; L6 -0.1,-8.9; L7 -0.1,-5.4; L8 -0.1,-1.9; L9 -0.1,1.6; L10 -0.1,5.1; L11 -0.1,8.6; L12 -0.1,12.1; L13 -0.1,15.6; L14 -0.1,19.1; L15 -0.1,22.6; L16 -0.1,26.1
